// Mitsubishi GX Works2 project: 日东运输机程序   PLC: FX3U/FX3UC

PROGRAM MAIN
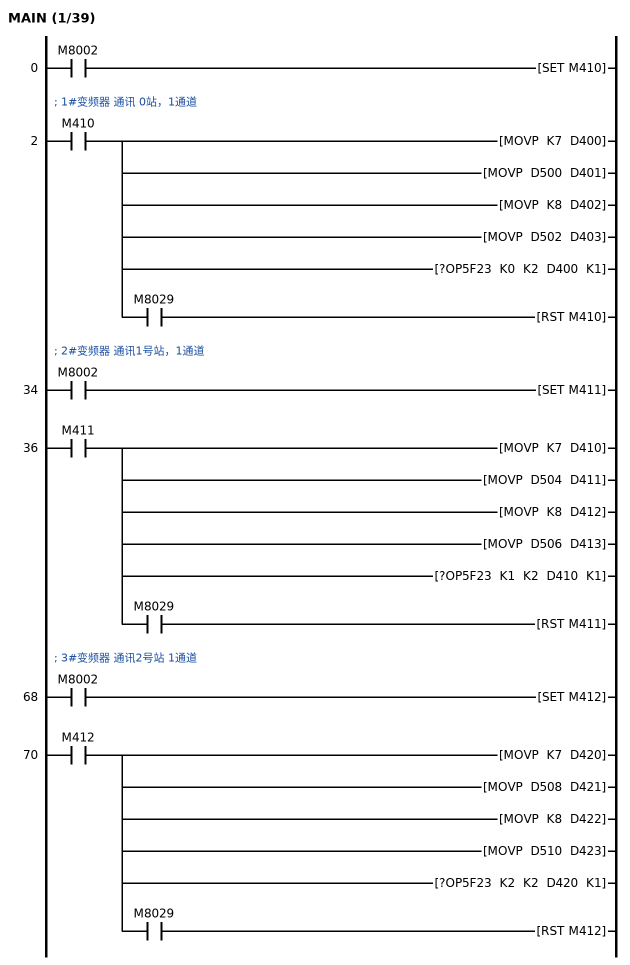
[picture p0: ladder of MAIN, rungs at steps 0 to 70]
0     LD      M8002
      SET     M410
; 1#变频器 通讯 0站，1通道
2     LD      M410
      MOVP    K7 D400
      MOVP    D500 D401
      MOVP    K8 D402
      MOVP    D502 D403
      ?OP5F23 K0 K2 D400 K1
        [note] 变频器参数成批写入
      AND     M8029
      RST     M410
; 2#变频器 通讯1号站，1通道
34    LD      M8002
      SET     M411
36    LD      M411
      MOVP    K7 D410
      MOVP    D504 D411
      MOVP    K8 D412
      MOVP    D506 D413
      ?OP5F23 K1 K2 D410 K1
        [note] 变频器参数成批写入
      AND     M8029
      RST     M411
; 3#变频器 通讯2号站 1通道
68    LD      M8002
      SET     M412
70    LD      M412
      MOVP    K7 D420
      MOVP    D508 D421
      MOVP    K8 D422
      MOVP    D510 D423
      ?OP5F23 K2 K2 D420 K1
        [note] 变频器参数成批写入
      AND     M8029
      RST     M412
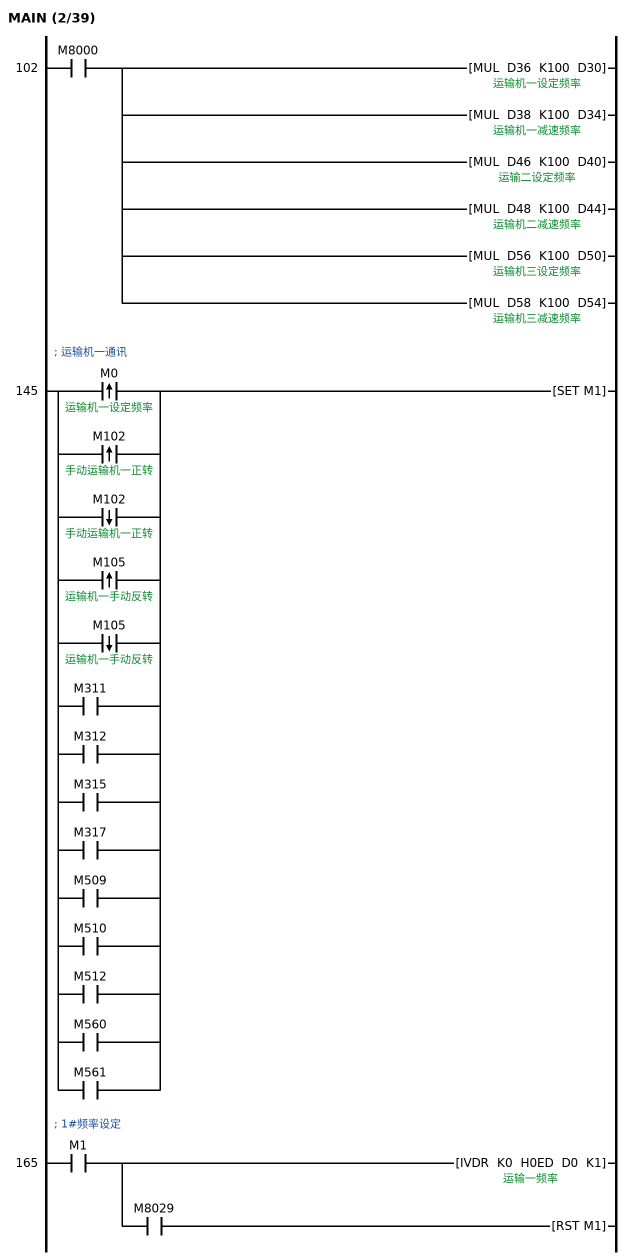
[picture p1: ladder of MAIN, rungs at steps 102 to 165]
102   LD      M8000
      MUL     D36 K100 D30  ; 运输机一设定频率
      MUL     D38 K100 D34  ; 运输机一减速频率
      MUL     D46 K100 D40  ; 运输二设定频率
      MUL     D48 K100 D44  ; 运输机二减速频率
      MUL     D56 K100 D50  ; 运输机三设定频率
      MUL     D58 K100 D54  ; 运输机三减速频率
; 运输机一通讯
145   LDP     M0  ; 运输机一设定频率
      ORP     M102  ; 手动运输机一正转
      ORF     M102  ; 手动运输机一正转
      ORP     M105  ; 运输机一手动反转
      ORF     M105  ; 运输机一手动反转
      OR      M311
      OR      M312
      OR      M315
      OR      M317
      OR      M509
      OR      M510
      OR      M512
      OR      M560
      OR      M561
      SET     M1
; 1#频率设定
165   LD      M1
      IVDR    K0 H0ED D0 K1  ; 运输一频率
      AND     M8029
      RST     M1
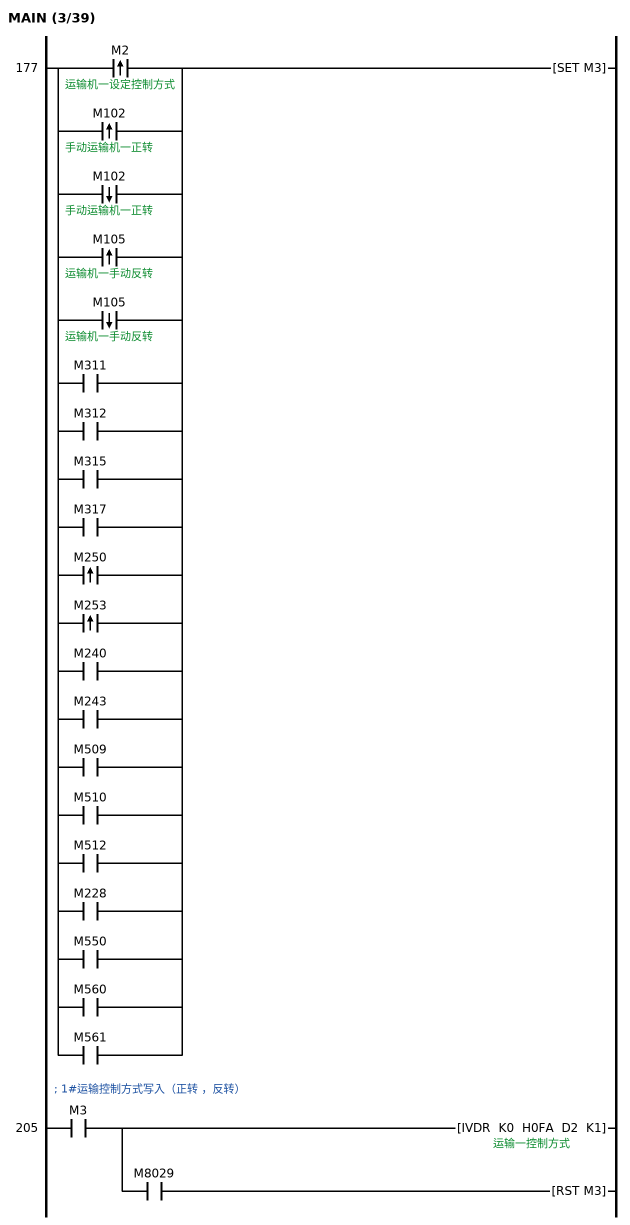
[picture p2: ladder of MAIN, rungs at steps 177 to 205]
177   LDP     M2  ; 运输机一设定控制方式
      ORP     M102  ; 手动运输机一正转
      ORF     M102  ; 手动运输机一正转
      ORP     M105  ; 运输机一手动反转
      ORF     M105  ; 运输机一手动反转
      OR      M311
      OR      M312
      OR      M315
      OR      M317
      ORP     M250
      ORP     M253
      OR      M240
      OR      M243
      OR      M509
      OR      M510
      OR      M512
      OR      M228
      OR      M550
      OR      M560
      OR      M561
      SET     M3
; 1#运输控制方式写入（正转 ，反转）
205   LD      M3
      IVDR    K0 H0FA D2 K1  ; 运输一控制方式
      AND     M8029
      RST     M3
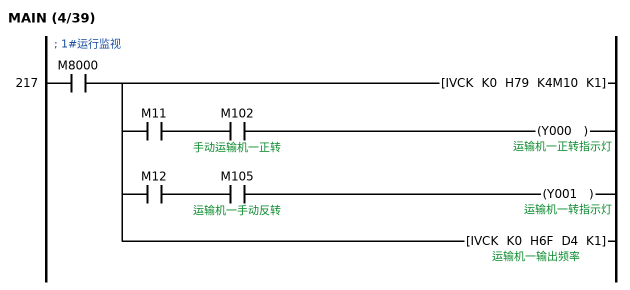
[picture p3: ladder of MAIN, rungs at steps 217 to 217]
; 1#运行监视
217   LD      M8000
      IVCK    K0 H79 K4M10 K1  ; 运输机一运行显示
      MPS
      AND     M11
      AND     M102  ; 手动运输机一正转
      OUT     Y000  ; 运输机一正转指示灯
      MRD
      AND     M12
      AND     M105  ; 运输机一手动反转
      OUT     Y001  ; 运输机一转指示灯
      MPP
      IVCK    K0 H6F D4 K1  ; 运输机一输出频率
        [note] 1#输出频率读取
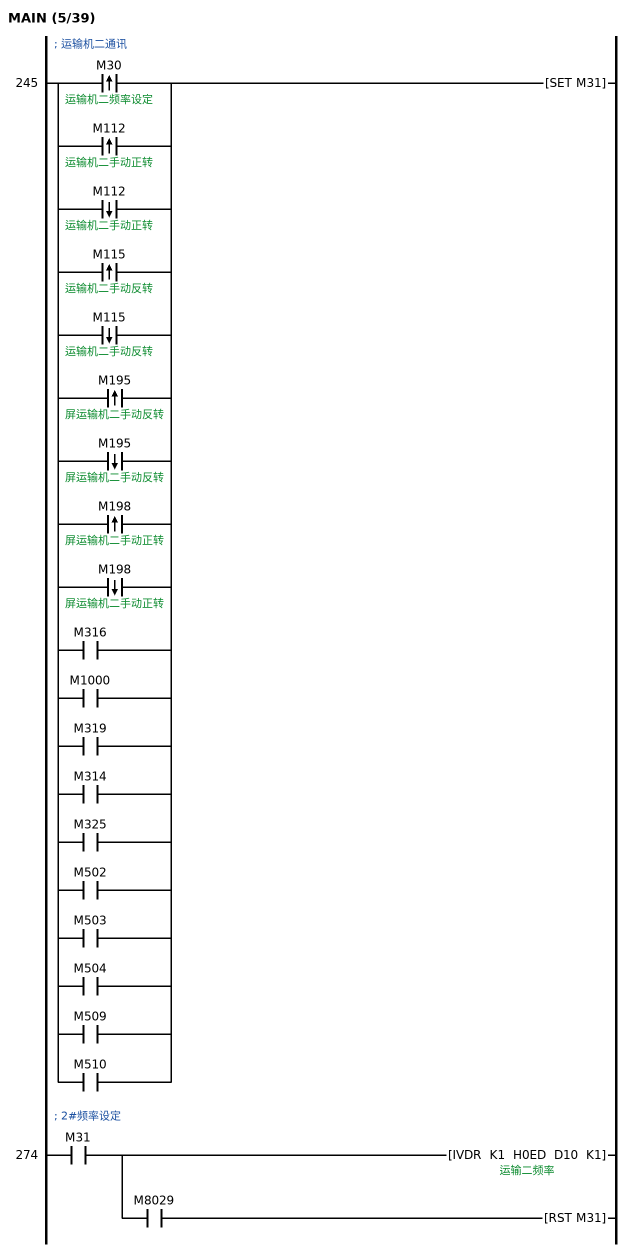
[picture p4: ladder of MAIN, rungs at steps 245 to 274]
; 运输机二通讯
245   LDP     M30  ; 运输机二频率设定
      ORP     M112  ; 运输机二手动正转
      ORF     M112  ; 运输机二手动正转
      ORP     M115  ; 运输机二手动反转
      ORF     M115  ; 运输机二手动反转
      ORP     M195  ; 屏运输机二手动反转
      ORF     M195  ; 屏运输机二手动反转
      ORP     M198  ; 屏运输机二手动正转
      ORF     M198  ; 屏运输机二手动正转
      OR      M316
      OR      M1000
      OR      M319
      OR      M314
      OR      M325
      OR      M502
      OR      M503
      OR      M504
      OR      M509
      OR      M510
      SET     M31
; 2#频率设定
274   LD      M31
      IVDR    K1 H0ED D10 K1  ; 运输二频率
      AND     M8029
      RST     M31
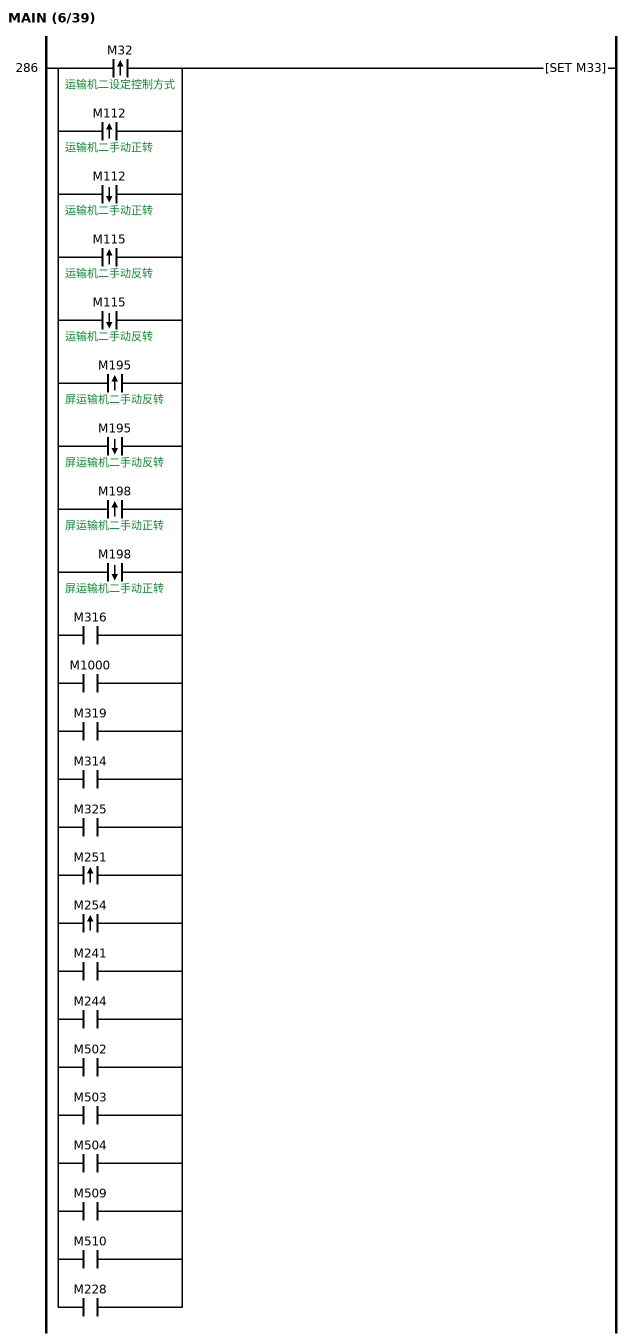
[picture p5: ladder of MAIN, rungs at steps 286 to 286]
286   LDP     M32  ; 运输机二设定控制方式
      ORP     M112  ; 运输机二手动正转
      ORF     M112  ; 运输机二手动正转
      ORP     M115  ; 运输机二手动反转
      ORF     M115  ; 运输机二手动反转
      ORP     M195  ; 屏运输机二手动反转
      ORF     M195  ; 屏运输机二手动反转
      ORP     M198  ; 屏运输机二手动正转
      ORF     M198  ; 屏运输机二手动正转
      OR      M316
      OR      M1000
      OR      M319
      OR      M314
      OR      M325
      ORP     M251
      ORP     M254
      OR      M241
      OR      M244
      OR      M502
      OR      M503
      OR      M504
      OR      M509
      OR      M510
      OR      M228
      SET     M33
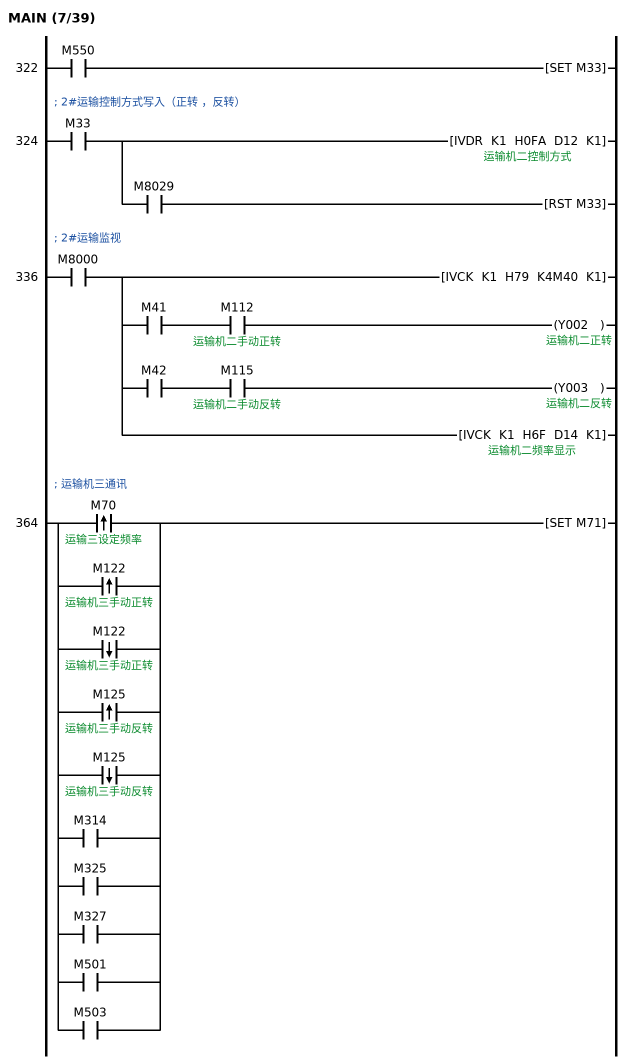
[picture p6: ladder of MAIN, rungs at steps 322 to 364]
322   LD      M550
      SET     M33
; 2#运输控制方式写入（正转 ，反转）
324   LD      M33
      IVDR    K1 H0FA D12 K1  ; 运输机二控制方式
      AND     M8029
      RST     M33
; 2#运输监视
336   LD      M8000
      IVCK    K1 H79 K4M40 K1  ; 运输机二运行显示
      MPS
      AND     M41
      AND     M112  ; 运输机二手动正转
      OUT     Y002  ; 运输机二正转
      MRD
      AND     M42
      AND     M115  ; 运输机二手动反转
      OUT     Y003  ; 运输机二反转
      MPP
      IVCK    K1 H6F D14 K1  ; 运输机二频率显示
; 运输机三通讯
364   LDP     M70  ; 运输三设定频率
      ORP     M122  ; 运输机三手动正转
      ORF     M122  ; 运输机三手动正转
      ORP     M125  ; 运输机三手动反转
      ORF     M125  ; 运输机三手动反转
      OR      M314
      OR      M325
      OR      M327
      OR      M501
      OR      M503
      SET     M71
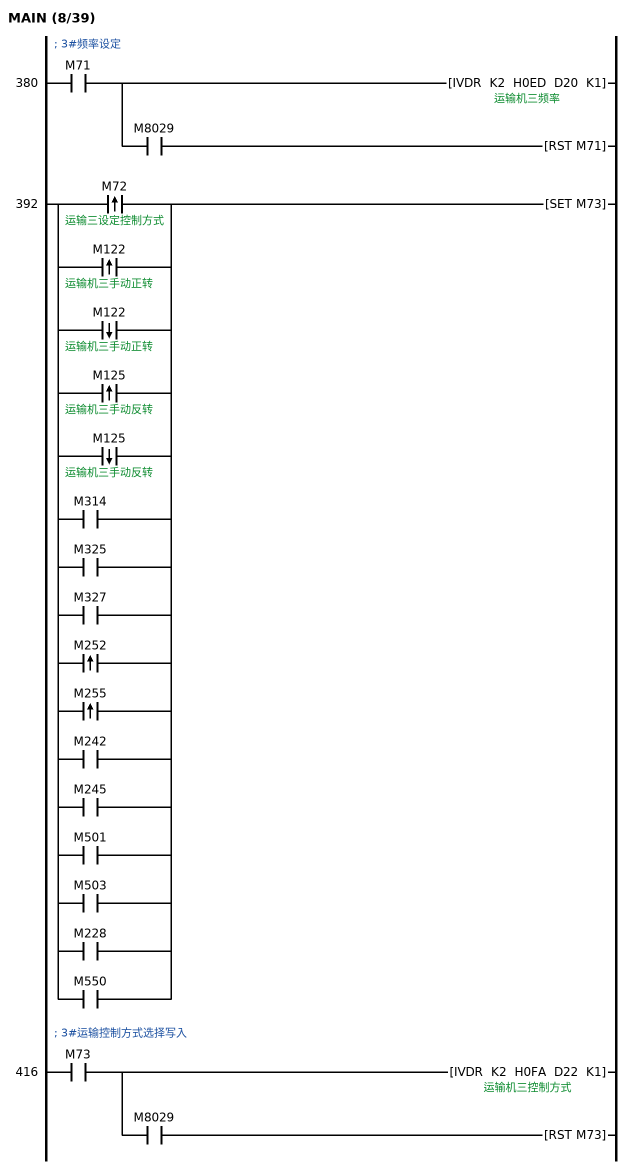
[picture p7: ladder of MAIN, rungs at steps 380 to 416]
; 3#频率设定
380   LD      M71
      IVDR    K2 H0ED D20 K1  ; 运输机三频率
      AND     M8029
      RST     M71
392   LDP     M72  ; 运输三设定控制方式
      ORP     M122  ; 运输机三手动正转
      ORF     M122  ; 运输机三手动正转
      ORP     M125  ; 运输机三手动反转
      ORF     M125  ; 运输机三手动反转
      OR      M314
      OR      M325
      OR      M327
      ORP     M252
      ORP     M255
      OR      M242
      OR      M245
      OR      M501
      OR      M503
      OR      M228
      OR      M550
      SET     M73
; 3#运输控制方式选择写入
416   LD      M73
      IVDR    K2 H0FA D22 K1  ; 运输机三控制方式
      AND     M8029
      RST     M73
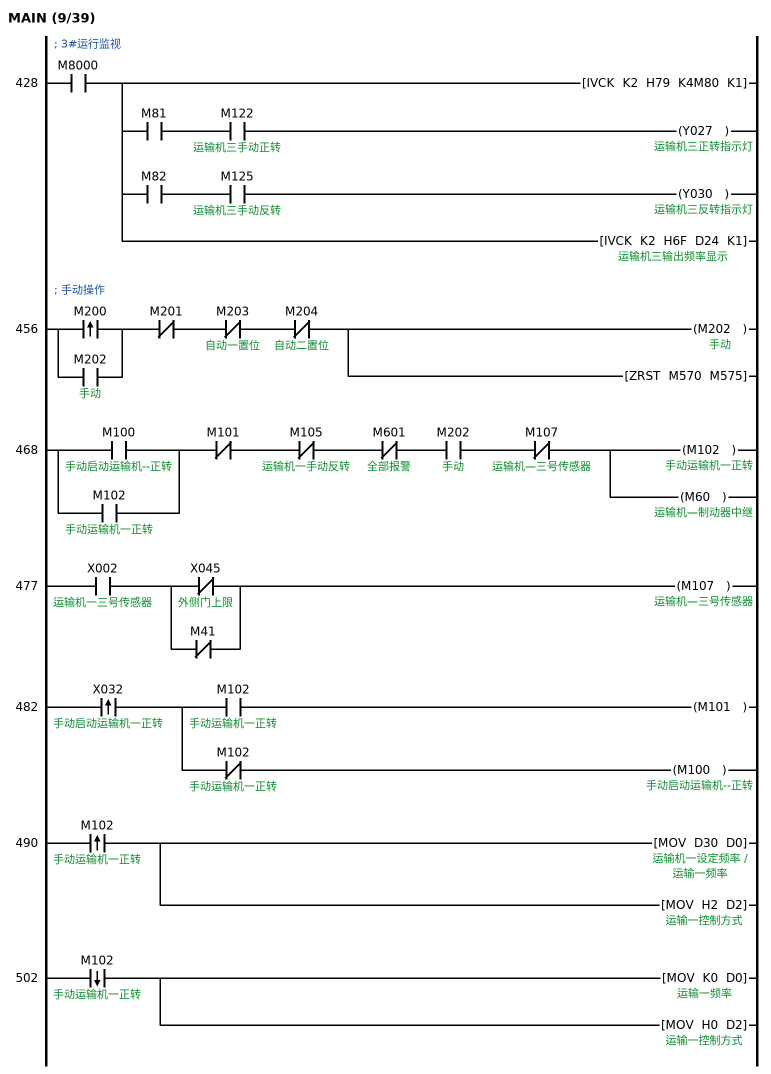
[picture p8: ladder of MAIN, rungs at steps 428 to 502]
; 3#运行监视
428   LD      M8000
      IVCK    K2 H79 K4M80 K1  ; 运输机三运行显示
      MPS
      AND     M81
      AND     M122  ; 运输机三手动正转
      OUT     Y027  ; 运输机三正转指示灯
      MRD
      AND     M82
      AND     M125  ; 运输机三手动反转
      OUT     Y030  ; 运输机三反转指示灯
      MPP
      IVCK    K2 H6F D24 K1  ; 运输机三输出频率显示
; 手动操作
456   LDP     M200
      OR      M202  ; 手动
      ANI     M201
      ANI     M203  ; 自动一置位
      ANI     M204  ; 自动二置位
      OUT     M202  ; 手动
      ZRST    M570 M575
468   LD      M100  ; 手动启动运输机--正转
      OR      M102  ; 手动运输机一正转
      ANI     M101
      ANI     M105  ; 运输机一手动反转
      ANI     M601  ; 全部报警
      AND     M202  ; 手动
      ANI     M107  ; 运输机—三号传感器
      OUT     M102  ; 手动运输机一正转
      OUT     M60  ; 运输机—制动器中继
477   LD      X002  ; 运输机一三号传感器
      LDI     X045  ; 外侧门上限
      ORI     M41
      ANB
      OUT     M107  ; 运输机—三号传感器
482   LDP     X032  ; 手动启动运输机一正转
      MPS
      AND     M102  ; 手动运输机一正转
      OUT     M101
      MPP
      ANI     M102  ; 手动运输机一正转
      OUT     M100  ; 手动启动运输机--正转
490   LDP     M102  ; 手动运输机一正转
      MOV     D30 D0
      MOV     H2 D2
        [note] 1#运输机正转写入
502   LDF     M102  ; 手动运输机一正转
      MOV     K0 D0
      MOV     H0 D2
        [note] 1#运输机停止写入
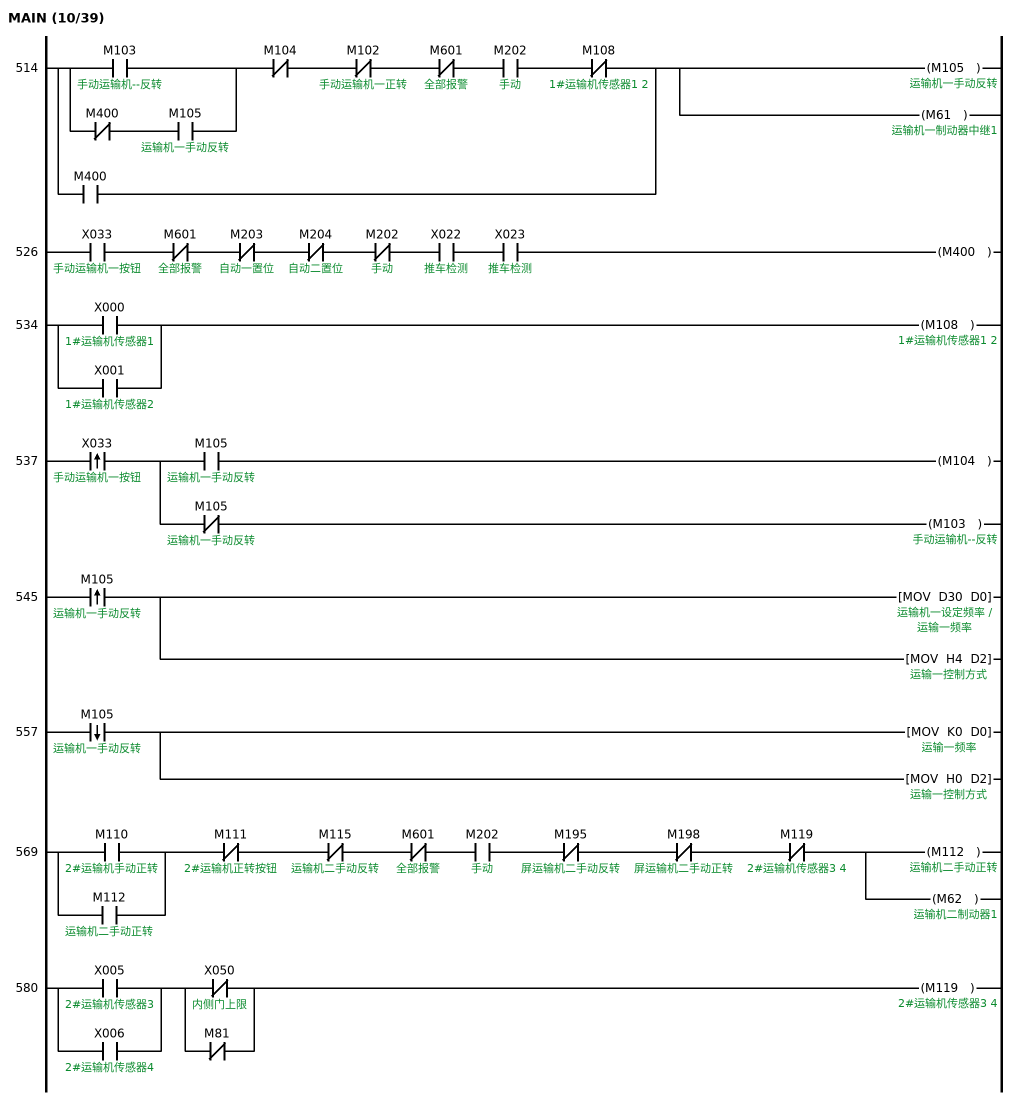
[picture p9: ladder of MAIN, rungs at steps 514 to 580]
514   LD      M103  ; 手动运输机--反转
      LDI     M400
      AND     M105  ; 运输机一手动反转
      ORB
      ANI     M104
      ANI     M102  ; 手动运输机一正转
      ANI     M601  ; 全部报警
      AND     M202  ; 手动
      ANI     M108  ; 1#运输机传感器1 2
      OR      M400
      OUT     M105  ; 运输机一手动反转
      OUT     M61  ; 运输机一制动器中继1
526   LD      X033  ; 手动运输机一按钮
      ANI     M601  ; 全部报警
      ANI     M203  ; 自动一置位
      ANI     M204  ; 自动二置位
      ANI     M202  ; 手动
      AND     X022  ; 推车检测
      AND     X023  ; 推车检测
      OUT     M400
534   LD      X000  ; 1#运输机传感器1
      OR      X001  ; 1#运输机传感器2
      OUT     M108  ; 1#运输机传感器1 2
537   LDP     X033  ; 手动运输机一按钮
      MPS
      AND     M105  ; 运输机一手动反转
      OUT     M104
      MPP
      ANI     M105  ; 运输机一手动反转
      OUT     M103  ; 手动运输机--反转
545   LDP     M105  ; 运输机一手动反转
      MOV     D30 D0
      MOV     H4 D2
        [note] 1#运输机反转写入
557   LDF     M105  ; 运输机一手动反转
      MOV     K0 D0
      MOV     H0 D2
        [note] 1#运输机停止写入
569   LD      M110  ; 2#运输机手动正转
      OR      M112  ; 运输机二手动正转
      ANI     M111  ; 2#运输机正转按钮
      ANI     M115  ; 运输机二手动反转
      ANI     M601  ; 全部报警
      AND     M202  ; 手动
      ANI     M195  ; 屏运输机二手动反转
      ANI     M198  ; 屏运输机二手动正转
      ANI     M119  ; 2#运输机传感器3 4
      OUT     M112  ; 运输机二手动正转
      OUT     M62  ; 运输机二制动器1
580   LD      X005  ; 2#运输机传感器3
      OR      X006  ; 2#运输机传感器4
      LDI     X050  ; 内侧门上限
      ORI     M81
      ANB
      OUT     M119  ; 2#运输机传感器3 4
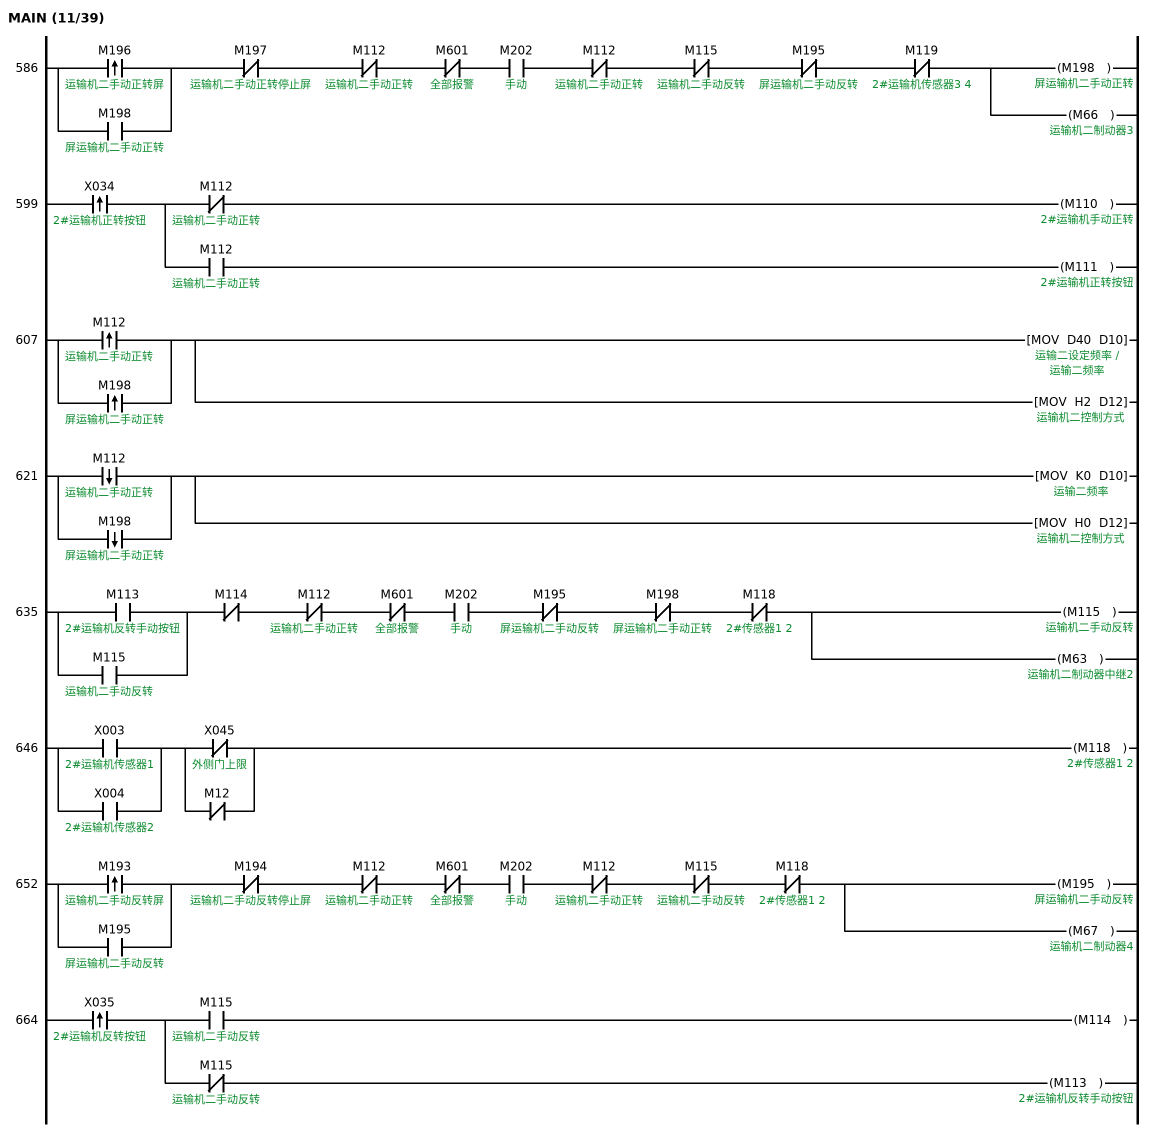
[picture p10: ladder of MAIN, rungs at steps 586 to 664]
586   LDP     M196  ; 运输机二手动正转屏
      OR      M198  ; 屏运输机二手动正转
      ANI     M197  ; 运输机二手动正转停止屏
      ANI     M112  ; 运输机二手动正转
      ANI     M601  ; 全部报警
      AND     M202  ; 手动
      ANI     M112  ; 运输机二手动正转
      ANI     M115  ; 运输机二手动反转
      ANI     M195  ; 屏运输机二手动反转
      ANI     M119  ; 2#运输机传感器3 4
      OUT     M198  ; 屏运输机二手动正转
      OUT     M66  ; 运输机二制动器3
599   LDP     X034  ; 2#运输机正转按钮
      MPS
      ANI     M112  ; 运输机二手动正转
      OUT     M110  ; 2#运输机手动正转
      MPP
      AND     M112  ; 运输机二手动正转
      OUT     M111  ; 2#运输机正转按钮
607   LDP     M112  ; 运输机二手动正转
      ORP     M198  ; 屏运输机二手动正转
      MOV     D40 D10
      MOV     H2 D12
        [note] 2#运输机正转写入
621   LDF     M112  ; 运输机二手动正转
      ORF     M198  ; 屏运输机二手动正转
      MOV     K0 D10
      MOV     H0 D12
        [note] 2#运输机停止写入
635   LD      M113  ; 2#运输机反转手动按钮
      OR      M115  ; 运输机二手动反转
      ANI     M114
      ANI     M112  ; 运输机二手动正转
      ANI     M601  ; 全部报警
      AND     M202  ; 手动
      ANI     M195  ; 屏运输机二手动反转
      ANI     M198  ; 屏运输机二手动正转
      ANI     M118  ; 2#传感器1 2
      OUT     M115  ; 运输机二手动反转
      OUT     M63  ; 运输机二制动器中继2
646   LD      X003  ; 2#运输机传感器1
      OR      X004  ; 2#运输机传感器2
      LDI     X045  ; 外侧门上限
      ORI     M12
      ANB
      OUT     M118  ; 2#传感器1 2
652   LDP     M193  ; 运输机二手动反转屏
      OR      M195  ; 屏运输机二手动反转
      ANI     M194  ; 运输机二手动反转停止屏
      ANI     M112  ; 运输机二手动正转
      ANI     M601  ; 全部报警
      AND     M202  ; 手动
      ANI     M112  ; 运输机二手动正转
      ANI     M115  ; 运输机二手动反转
      ANI     M118  ; 2#传感器1 2
      OUT     M195  ; 屏运输机二手动反转
      OUT     M67  ; 运输机二制动器4
664   LDP     X035  ; 2#运输机反转按钮
      MPS
      AND     M115  ; 运输机二手动反转
      OUT     M114
      MPP
      ANI     M115  ; 运输机二手动反转
      OUT     M113  ; 2#运输机反转手动按钮
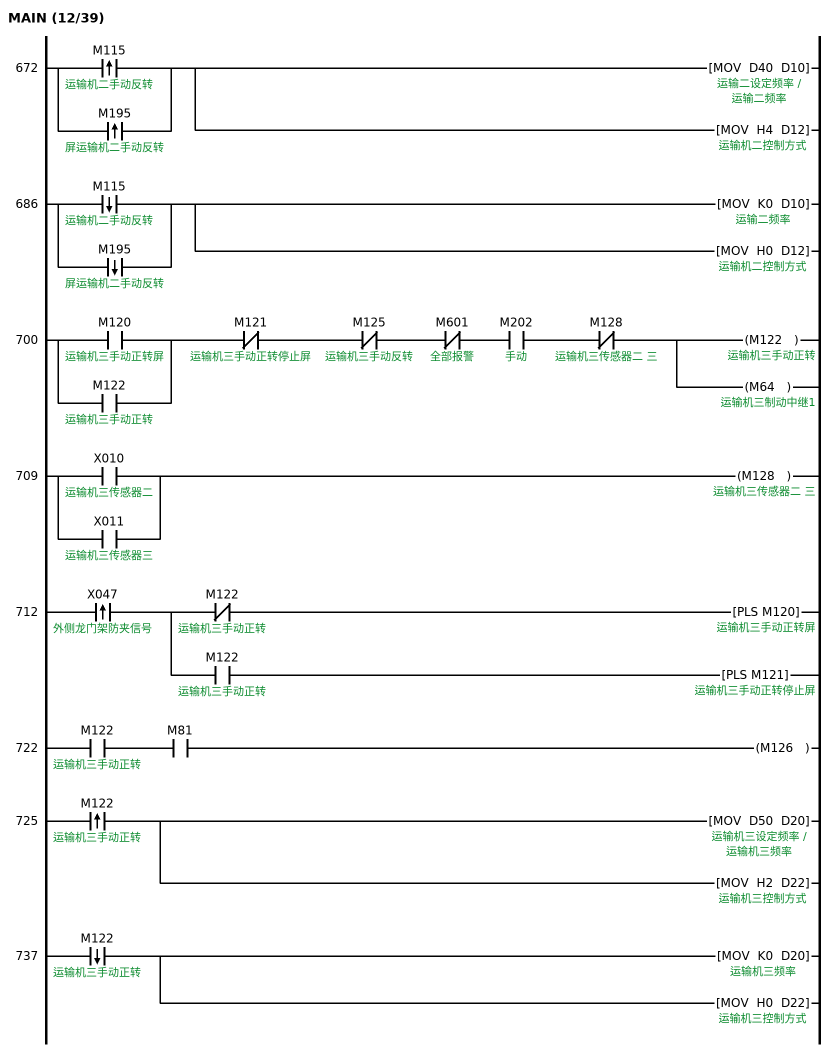
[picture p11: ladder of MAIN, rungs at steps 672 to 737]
672   LDP     M115  ; 运输机二手动反转
      ORP     M195  ; 屏运输机二手动反转
      MOV     D40 D10
      MOV     H4 D12
        [note] 2#运输机反转写入
686   LDF     M115  ; 运输机二手动反转
      ORF     M195  ; 屏运输机二手动反转
      MOV     K0 D10
      MOV     H0 D12
        [note] 2#运输机停止写入
700   LD      M120  ; 运输机三手动正转屏
      OR      M122  ; 运输机三手动正转
      ANI     M121  ; 运输机三手动正转停止屏
      ANI     M125  ; 运输机三手动反转
      ANI     M601  ; 全部报警
      AND     M202  ; 手动
      ANI     M128  ; 运输机三传感器二 三
      OUT     M122  ; 运输机三手动正转
      OUT     M64  ; 运输机三制动中继1
709   LD      X010  ; 运输机三传感器二
      OR      X011  ; 运输机三传感器三
      OUT     M128  ; 运输机三传感器二 三
712   LDP     X047  ; 外侧龙门架防夹信号
      MPS
      ANI     M122  ; 运输机三手动正转
      PLS     M120  ; 运输机三手动正转屏
      MPP
      AND     M122  ; 运输机三手动正转
      PLS     M121  ; 运输机三手动正转停止屏
722   LD      M122  ; 运输机三手动正转
      AND     M81
      OUT     M126
725   LDP     M122  ; 运输机三手动正转
      MOV     D50 D20
      MOV     H2 D22
        [note] 3#运输机正转写入
737   LDF     M122  ; 运输机三手动正转
      MOV     K0 D20
      MOV     H0 D22
        [note] 3#运输机停止写入
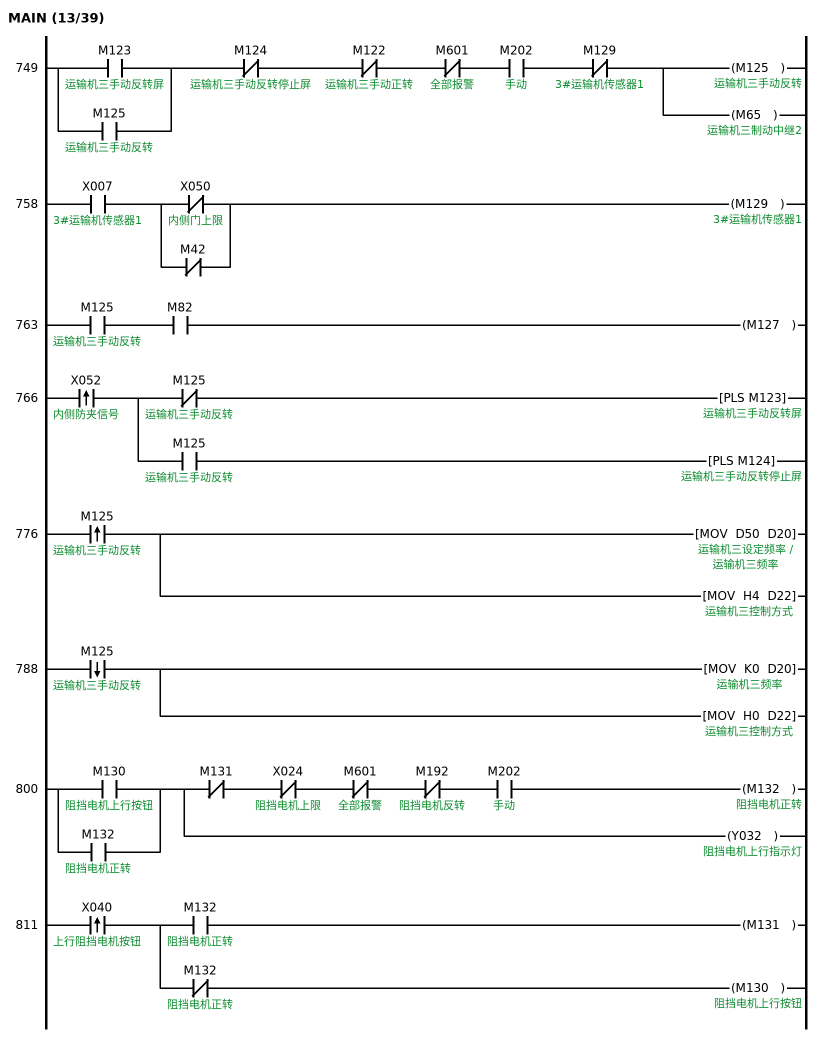
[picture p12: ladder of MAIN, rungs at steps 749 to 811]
749   LD      M123  ; 运输机三手动反转屏
      OR      M125  ; 运输机三手动反转
      ANI     M124  ; 运输机三手动反转停止屏
      ANI     M122  ; 运输机三手动正转
      ANI     M601  ; 全部报警
      AND     M202  ; 手动
      ANI     M129  ; 3#运输机传感器1
      OUT     M125  ; 运输机三手动反转
      OUT     M65  ; 运输机三制动中继2
758   LD      X007  ; 3#运输机传感器1
      LDI     X050  ; 内侧门上限
      ORI     M42
      ANB
      OUT     M129  ; 3#运输机传感器1
763   LD      M125  ; 运输机三手动反转
      AND     M82
      OUT     M127
766   LDP     X052  ; 内侧防夹信号
      MPS
      ANI     M125  ; 运输机三手动反转
      PLS     M123  ; 运输机三手动反转屏
      MPP
      AND     M125  ; 运输机三手动反转
      PLS     M124  ; 运输机三手动反转停止屏
776   LDP     M125  ; 运输机三手动反转
      MOV     D50 D20
      MOV     H4 D22
        [note] 3#运输机反转写入
788   LDF     M125  ; 运输机三手动反转
      MOV     K0 D20
      MOV     H0 D22
        [note] 3#运输机停止写入
800   LD      M130  ; 阻挡电机上行按钮
      OR      M132  ; 阻挡电机正转
      MPS
      ANI     M131
      ANI     X024  ; 阻挡电机上限
      ANI     M601  ; 全部报警
      ANI     M192  ; 阻挡电机反转
      AND     M202  ; 手动
      OUT     M132  ; 阻挡电机正转
      MPP
      OUT     Y032  ; 阻挡电机上行指示灯
811   LDP     X040  ; 上行阻挡电机按钮
      MPS
      AND     M132  ; 阻挡电机正转
      OUT     M131
      MPP
      ANI     M132  ; 阻挡电机正转
      OUT     M130  ; 阻挡电机上行按钮
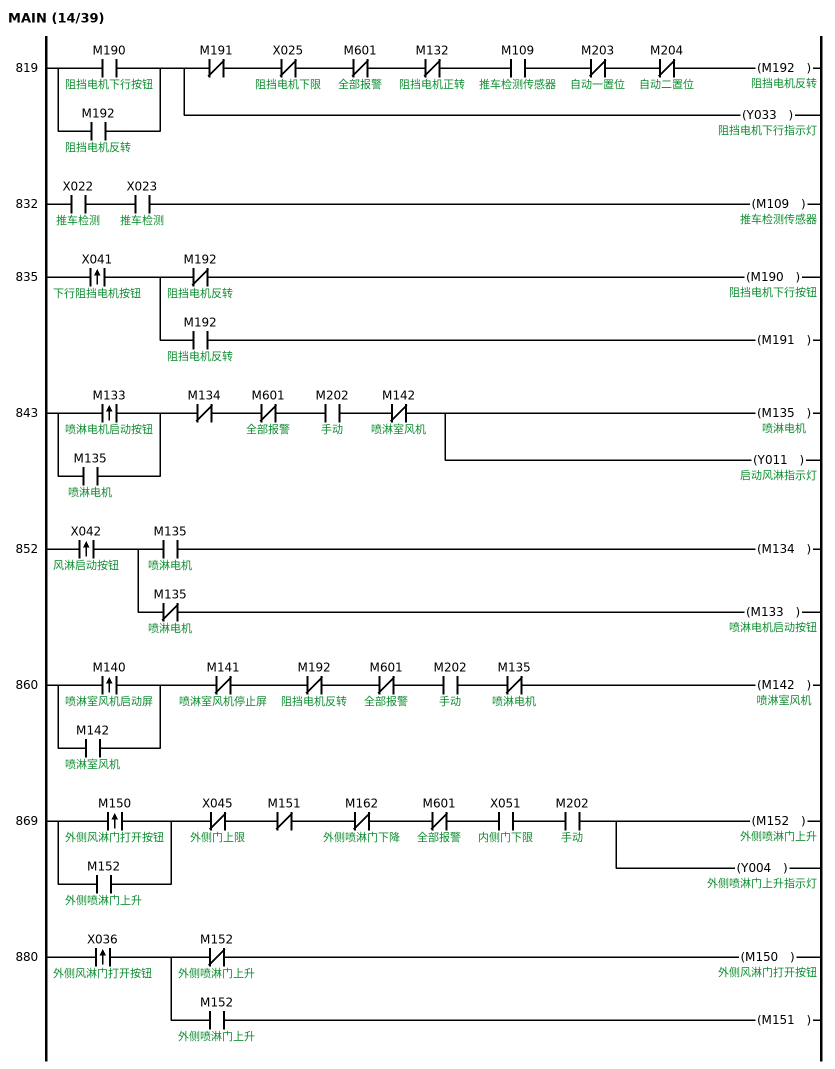
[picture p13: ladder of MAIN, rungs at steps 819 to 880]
819   LD      M190  ; 阻挡电机下行按钮
      OR      M192  ; 阻挡电机反转
      MPS
      ANI     M191
      ANI     X025  ; 阻挡电机下限
      ANI     M601  ; 全部报警
      ANI     M132  ; 阻挡电机正转
      AND     M109  ; 推车检测传感器
      ANI     M203  ; 自动一置位
      ANI     M204  ; 自动二置位
      OUT     M192  ; 阻挡电机反转
      MPP
      OUT     Y033  ; 阻挡电机下行指示灯
832   LD      X022  ; 推车检测
      AND     X023  ; 推车检测
      OUT     M109  ; 推车检测传感器
835   LDP     X041  ; 下行阻挡电机按钮
      MPS
      ANI     M192  ; 阻挡电机反转
      OUT     M190  ; 阻挡电机下行按钮
      MPP
      AND     M192  ; 阻挡电机反转
      OUT     M191
843   LDP     M133  ; 喷淋电机启动按钮
      OR      M135  ; 喷淋电机
      ANI     M134
      ANI     M601  ; 全部报警
      AND     M202  ; 手动
      ANI     M142  ; 喷淋室风机
      OUT     M135  ; 喷淋电机
      OUT     Y011  ; 启动风淋指示灯
852   LDP     X042  ; 风淋启动按钮
      MPS
      AND     M135  ; 喷淋电机
      OUT     M134
      MPP
      ANI     M135  ; 喷淋电机
      OUT     M133  ; 喷淋电机启动按钮
860   LDP     M140  ; 喷淋室风机启动屏
      OR      M142  ; 喷淋室风机
      ANI     M141  ; 喷淋室风机停止屏
      ANI     M192  ; 阻挡电机反转
      ANI     M601  ; 全部报警
      AND     M202  ; 手动
      ANI     M135  ; 喷淋电机
      OUT     M142  ; 喷淋室风机
869   LDP     M150  ; 外侧风淋门打开按钮
      OR      M152  ; 外侧喷淋门上升
      ANI     X045  ; 外侧门上限
      ANI     M151
      ANI     M162  ; 外侧喷淋门下降
      ANI     M601  ; 全部报警
      AND     X051  ; 内侧门下限
      AND     M202  ; 手动
      OUT     M152  ; 外侧喷淋门上升
      OUT     Y004  ; 外侧喷淋门上升指示灯
880   LDP     X036  ; 外侧风淋门打开按钮
      MPS
      ANI     M152  ; 外侧喷淋门上升
      OUT     M150  ; 外侧风淋门打开按钮
      MPP
      AND     M152  ; 外侧喷淋门上升
      OUT     M151
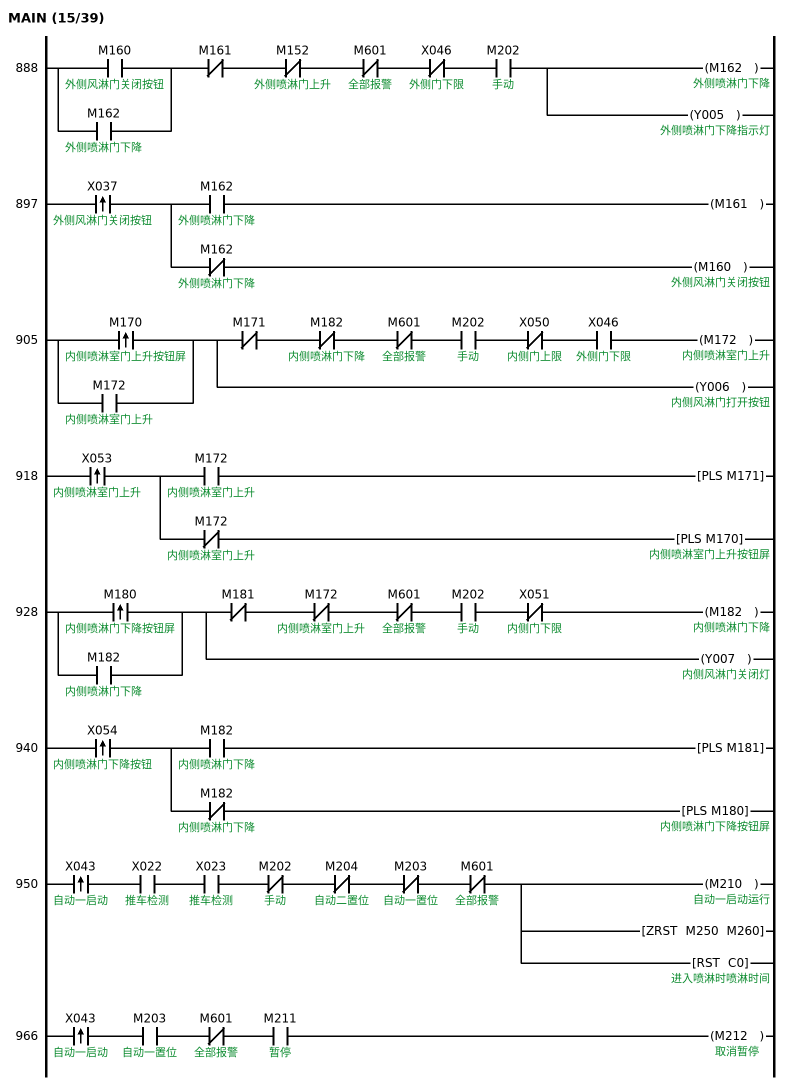
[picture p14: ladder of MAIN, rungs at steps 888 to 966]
888   LD      M160  ; 外侧风淋门关闭按钮
      OR      M162  ; 外侧喷淋门下降
      ANI     M161
      ANI     M152  ; 外侧喷淋门上升
      ANI     M601  ; 全部报警
      ANI     X046  ; 外侧门下限
      AND     M202  ; 手动
      OUT     M162  ; 外侧喷淋门下降
      OUT     Y005  ; 外侧喷淋门下降指示灯
897   LDP     X037  ; 外侧风淋门关闭按钮
      MPS
      AND     M162  ; 外侧喷淋门下降
      OUT     M161
      MPP
      ANI     M162  ; 外侧喷淋门下降
      OUT     M160  ; 外侧风淋门关闭按钮
905   LDP     M170  ; 内侧喷淋室门上升按钮屏
      OR      M172  ; 内侧喷淋室门上升
      MPS
      ANI     M171
      ANI     M182  ; 内侧喷淋门下降
      ANI     M601  ; 全部报警
      AND     M202  ; 手动
      ANI     X050  ; 内侧门上限
      AND     X046  ; 外侧门下限
      OUT     M172  ; 内侧喷淋室门上升
      MPP
      OUT     Y006  ; 内侧风淋门打开按钮
918   LDP     X053  ; 内侧喷淋室门上升
      MPS
      AND     M172  ; 内侧喷淋室门上升
      PLS     M171
      MPP
      ANI     M172  ; 内侧喷淋室门上升
      PLS     M170  ; 内侧喷淋室门上升按钮屏
928   LDP     M180  ; 内侧喷淋门下降按钮屏
      OR      M182  ; 内侧喷淋门下降
      MPS
      ANI     M181
      ANI     M172  ; 内侧喷淋室门上升
      ANI     M601  ; 全部报警
      AND     M202  ; 手动
      ANI     X051  ; 内侧门下限
      OUT     M182  ; 内侧喷淋门下降
      MPP
      OUT     Y007  ; 内侧风淋门关闭灯
940   LDP     X054  ; 内侧喷淋门下降按钮
      MPS
      AND     M182  ; 内侧喷淋门下降
      PLS     M181
      MPP
      ANI     M182  ; 内侧喷淋门下降
      PLS     M180  ; 内侧喷淋门下降按钮屏
950   LDP     X043  ; 自动一启动
      AND     X022  ; 推车检测
      AND     X023  ; 推车检测
      ANI     M202  ; 手动
      ANI     M204  ; 自动二置位
      ANI     M203  ; 自动一置位
      ANI     M601  ; 全部报警
      OUT     M210  ; 自动一启动运行
      ZRST    M250 M260
      RST     C0  ; 进入喷淋时喷淋时间
966   LDP     X043  ; 自动一启动
      AND     M203  ; 自动一置位
      ANI     M601  ; 全部报警
      AND     M211  ; 暂停
      OUT     M212  ; 取消暂停
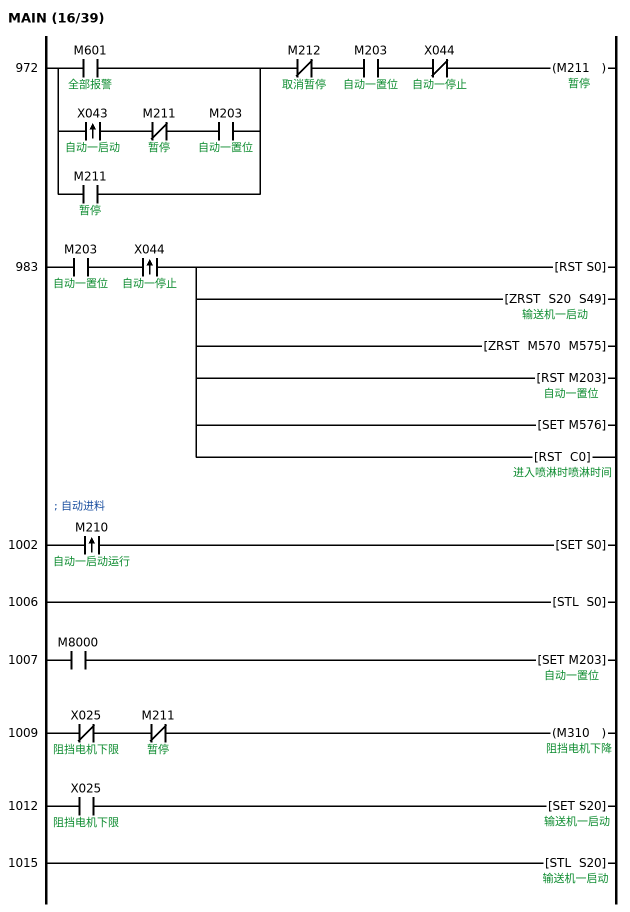
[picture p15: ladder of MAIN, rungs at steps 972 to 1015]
972   LD      M601  ; 全部报警
      LDP     X043  ; 自动一启动
      ANI     M211  ; 暂停
      AND     M203  ; 自动一置位
      ORB
      OR      M211  ; 暂停
      ANI     M212  ; 取消暂停
      AND     M203  ; 自动一置位
      ANI     X044  ; 自动一停止
      OUT     M211  ; 暂停
983   LD      M203  ; 自动一置位
      ANDP    X044  ; 自动一停止
      RST     S0
      ZRST    S20 S49  ; 输送机一启动
      ZRST    M570 M575
      RST     M203  ; 自动一置位
      SET     M576
      RST     C0  ; 进入喷淋时喷淋时间
; 自动进料
1002  LDP     M210  ; 自动一启动运行
      SET     S0
1006  STL     S0
1007  LD      M8000
      SET     M203  ; 自动一置位
1009  LDI     X025  ; 阻挡电机下限
      ANI     M211  ; 暂停
      OUT     M310  ; 阻挡电机下降
1012  LD      X025  ; 阻挡电机下限
      SET     S20  ; 输送机一启动
1015  STL     S20
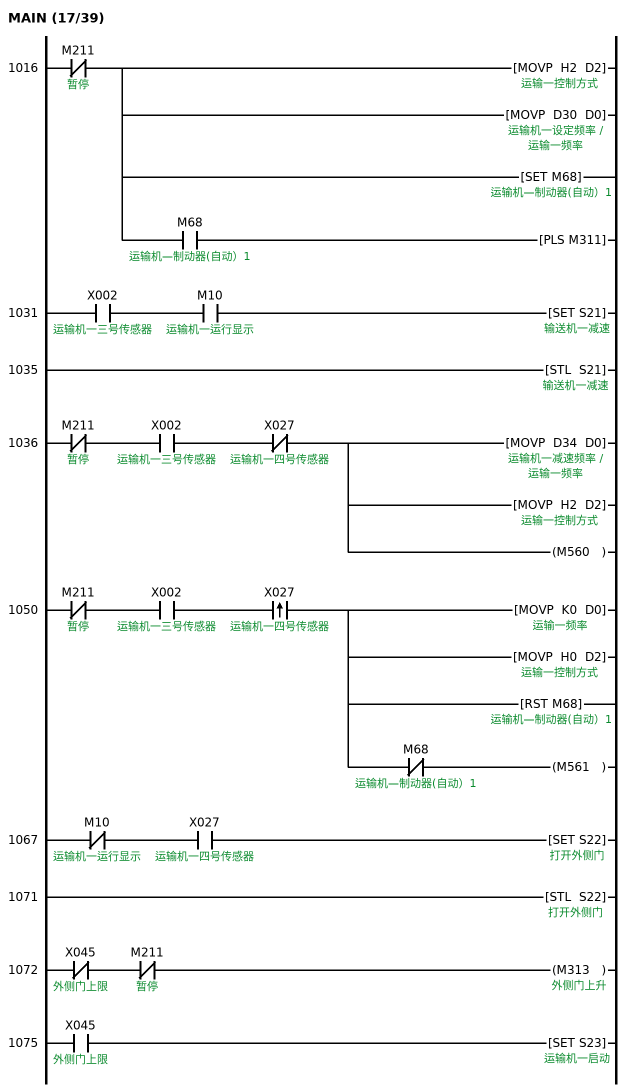
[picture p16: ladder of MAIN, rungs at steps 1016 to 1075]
1016  LDI     M211  ; 暂停
      MOVP    H2 D2
        [note] 1#运输机正转写入
      MOVP    D30 D0
      SET     M68  ; 运输机—制动器(自动）1
      AND     M68  ; 运输机—制动器(自动）1
      PLS     M311
1031  LD      X002  ; 运输机一三号传感器
      AND     M10  ; 运输机一运行显示
      SET     S21  ; 输送机一减速
1035  STL     S21
1036  LDI     M211  ; 暂停
      AND     X002  ; 运输机一三号传感器
      ANI     X027  ; 运输机一四号传感器
      MOVP    D34 D0
      MOVP    H2 D2
        [note] 1#运输机正转写入
      OUT     M560
1050  LDI     M211  ; 暂停
      AND     X002  ; 运输机一三号传感器
      ANDP    X027  ; 运输机一四号传感器
      MOVP    K0 D0
      MOVP    H0 D2
      RST     M68  ; 运输机—制动器(自动）1
      ANI     M68  ; 运输机—制动器(自动）1
      OUT     M561
1067  LDI     M10  ; 运输机一运行显示
      AND     X027  ; 运输机一四号传感器
      SET     S22  ; 打开外侧门
1071  STL     S22
1072  LDI     X045  ; 外侧门上限
      ANI     M211  ; 暂停
      OUT     M313  ; 外侧门上升
1075  LD      X045  ; 外侧门上限
      SET     S23  ; 运输机一启动
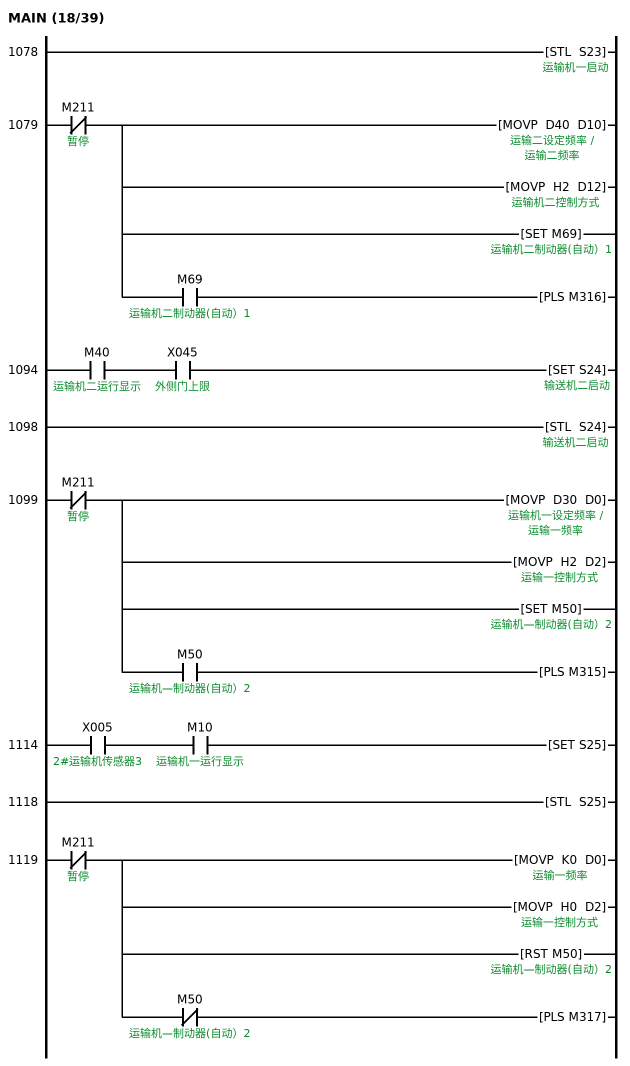
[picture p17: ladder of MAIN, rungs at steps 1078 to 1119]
1078  STL     S23
1079  LDI     M211  ; 暂停
      MOVP    D40 D10
      MOVP    H2 D12
        [note] 2#运输机正转写入
      SET     M69  ; 运输机二制动器(自动）1
      AND     M69  ; 运输机二制动器(自动）1
      PLS     M316
1094  LD      M40  ; 运输机二运行显示
      AND     X045  ; 外侧门上限
      SET     S24  ; 输送机二启动
1098  STL     S24
1099  LDI     M211  ; 暂停
      MOVP    D30 D0
      MOVP    H2 D2
        [note] 1#运输机正转写入
      SET     M50  ; 运输机—制动器(自动）2
      AND     M50  ; 运输机—制动器(自动）2
      PLS     M315
1114  LD      X005  ; 2#运输机传感器3
      AND     M10  ; 运输机一运行显示
      SET     S25
1118  STL     S25
1119  LDI     M211  ; 暂停
      MOVP    K0 D0
      MOVP    H0 D2
        [note] 1#运输机停止写入
      RST     M50  ; 运输机—制动器(自动）2
      ANI     M50  ; 运输机—制动器(自动）2
      PLS     M317
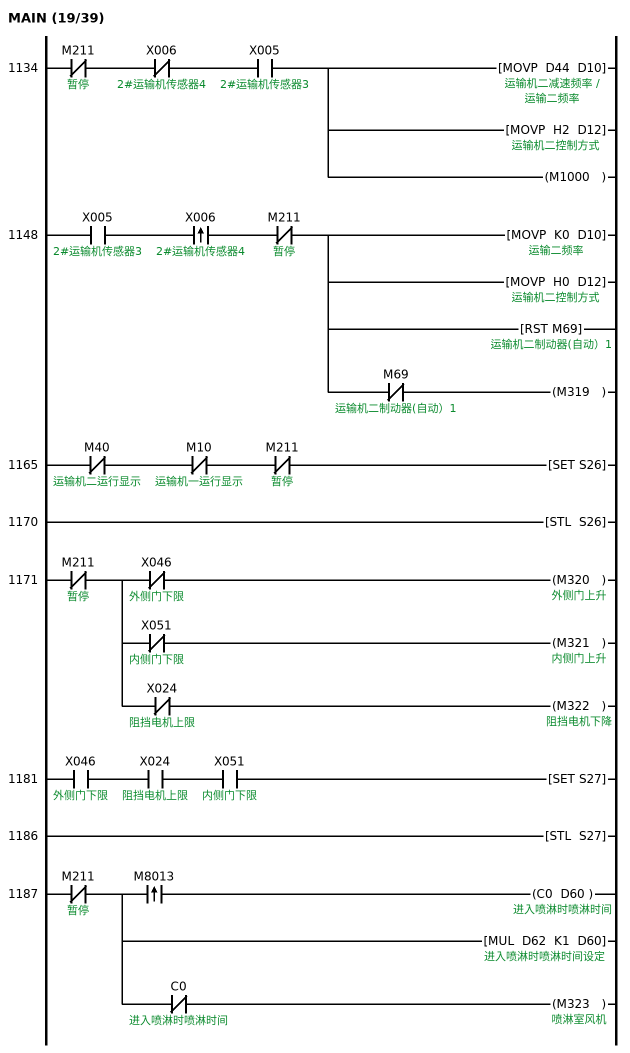
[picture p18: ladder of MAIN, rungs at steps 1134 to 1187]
1134  LDI     M211  ; 暂停
      ANI     X006  ; 2#运输机传感器4
      AND     X005  ; 2#运输机传感器3
      MOVP    D44 D10
      MOVP    H2 D12
        [note] 2#运输机正转写入
      OUT     M1000
1148  LD      X005  ; 2#运输机传感器3
      ANDP    X006  ; 2#运输机传感器4
      ANI     M211  ; 暂停
      MOVP    K0 D10
      MOVP    H0 D12
        [note] 2#运输机停止写入
      RST     M69  ; 运输机二制动器(自动）1
      ANI     M69  ; 运输机二制动器(自动）1
      OUT     M319
1165  LDI     M40  ; 运输机二运行显示
      ANI     M10  ; 运输机一运行显示
      ANI     M211  ; 暂停
      SET     S26
1170  STL     S26
1171  LDI     M211  ; 暂停
      MPS
      ANI     X046  ; 外侧门下限
      OUT     M320  ; 外侧门上升
      MRD
      ANI     X051  ; 内侧门下限
      OUT     M321  ; 内侧门上升
      MPP
      ANI     X024  ; 阻挡电机上限
      OUT     M322  ; 阻挡电机下降
1181  LD      X046  ; 外侧门下限
      AND     X024  ; 阻挡电机上限
      AND     X051  ; 内侧门下限
      SET     S27
1186  STL     S27
1187  LDI     M211  ; 暂停
      MPS
      ANDP    M8013
      OUT     C0 D60  ; 进入喷淋时喷淋时间
      MPP
      MUL     D62 K1 D60  ; 进入喷淋时喷淋时间设定
      ANI     C0  ; 进入喷淋时喷淋时间
      OUT     M323  ; 喷淋室风机
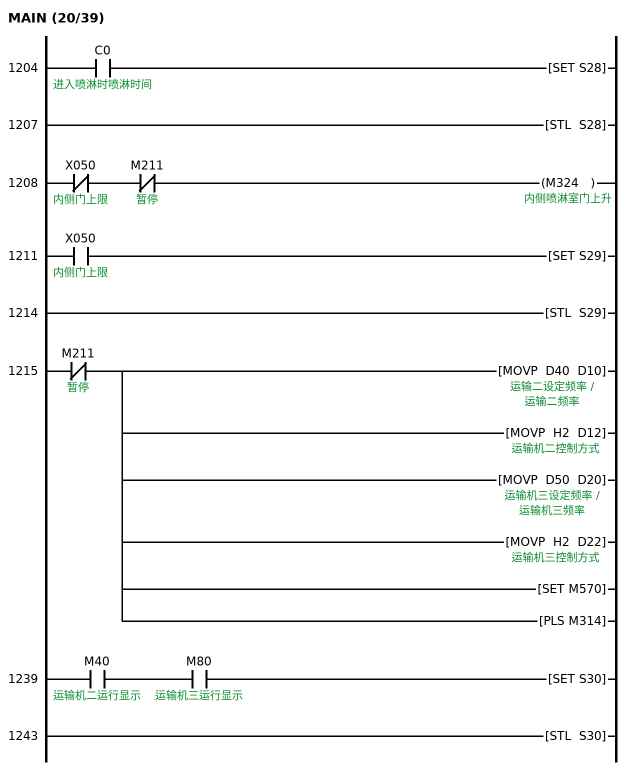
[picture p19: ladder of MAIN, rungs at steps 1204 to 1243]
1204  LD      C0  ; 进入喷淋时喷淋时间
      SET     S28
1207  STL     S28
1208  LDI     X050  ; 内侧门上限
      ANI     M211  ; 暂停
      OUT     M324  ; 内侧喷淋室门上升
1211  LD      X050  ; 内侧门上限
      SET     S29
        [note] 内侧门打开到位
1214  STL     S29
1215  LDI     M211  ; 暂停
      MOVP    D40 D10
      MOVP    H2 D12
        [note] 2#运输机正转写入
      MOVP    D50 D20
      MOVP    H2 D22
        [note] 3#运输机正转写入
      SET     M570
      PLS     M314
1239  LD      M40  ; 运输机二运行显示
      AND     M80  ; 运输机三运行显示
      SET     S30
1243  STL     S30
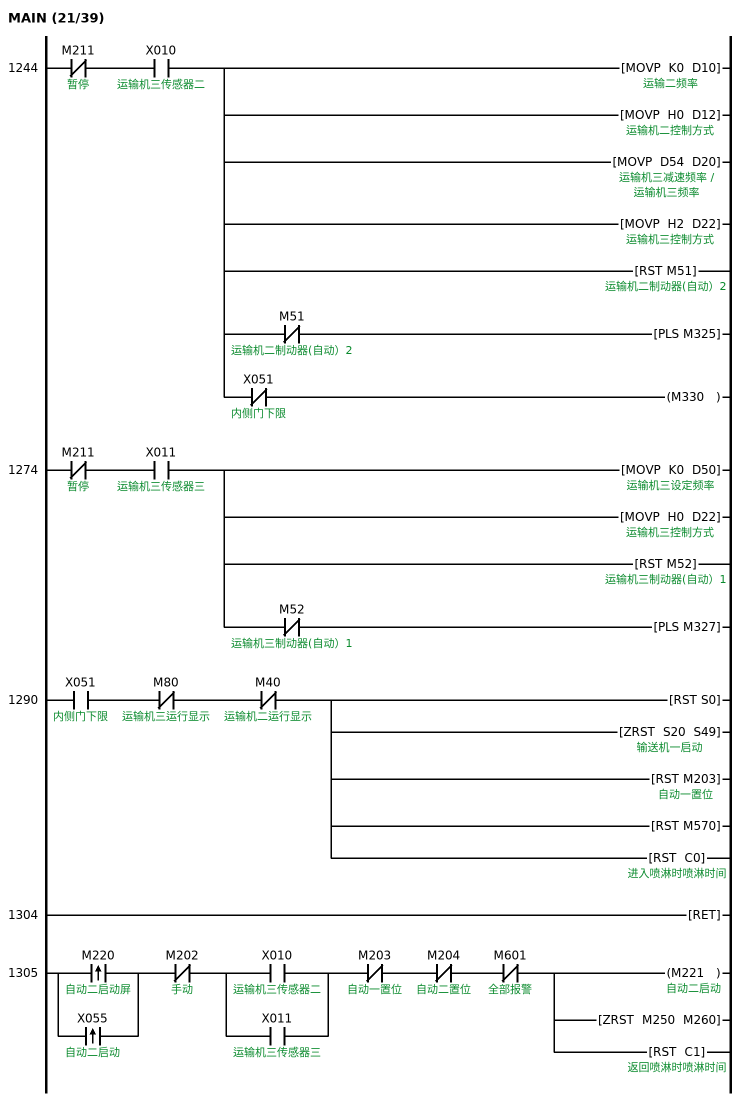
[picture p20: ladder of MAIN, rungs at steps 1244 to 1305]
1244  LDI     M211  ; 暂停
      AND     X010  ; 运输机三传感器二
      MOVP    K0 D10
      MOVP    H0 D12
        [note] 2#运输机停止写入
      MOVP    D54 D20
      MOVP    H2 D22
        [note] 3#运输机正转写入
      RST     M51  ; 运输机二制动器(自动）2
      MPS
      ANI     M51  ; 运输机二制动器(自动）2
      PLS     M325
      MPP
      ANI     X051  ; 内侧门下限
      OUT     M330
1274  LDI     M211  ; 暂停
      AND     X011  ; 运输机三传感器三
      MOVP    K0 D50
      MOVP    H0 D22
        [note] 3#运输机停止写入
      RST     M52  ; 运输机三制动器(自动）1
      ANI     M52  ; 运输机三制动器(自动）1
      PLS     M327
1290  LD      X051  ; 内侧门下限
      ANI     M80  ; 运输机三运行显示
      ANI     M40  ; 运输机二运行显示
      RST     S0
      ZRST    S20 S49
      RST     M203  ; 自动一置位
      RST     M570
      RST     C0  ; 进入喷淋时喷淋时间
1304  RET
1305  LDP     M220  ; 自动二启动屏
      ORP     X055  ; 自动二启动
      ANI     M202  ; 手动
      LD      X010  ; 运输机三传感器二
      OR      X011  ; 运输机三传感器三
      ANB
      ANI     M203  ; 自动一置位
      ANI     M204  ; 自动二置位
      ANI     M601  ; 全部报警
      OUT     M221  ; 自动二启动
      ZRST    M250 M260
      RST     C1  ; 返回喷淋时喷淋时间
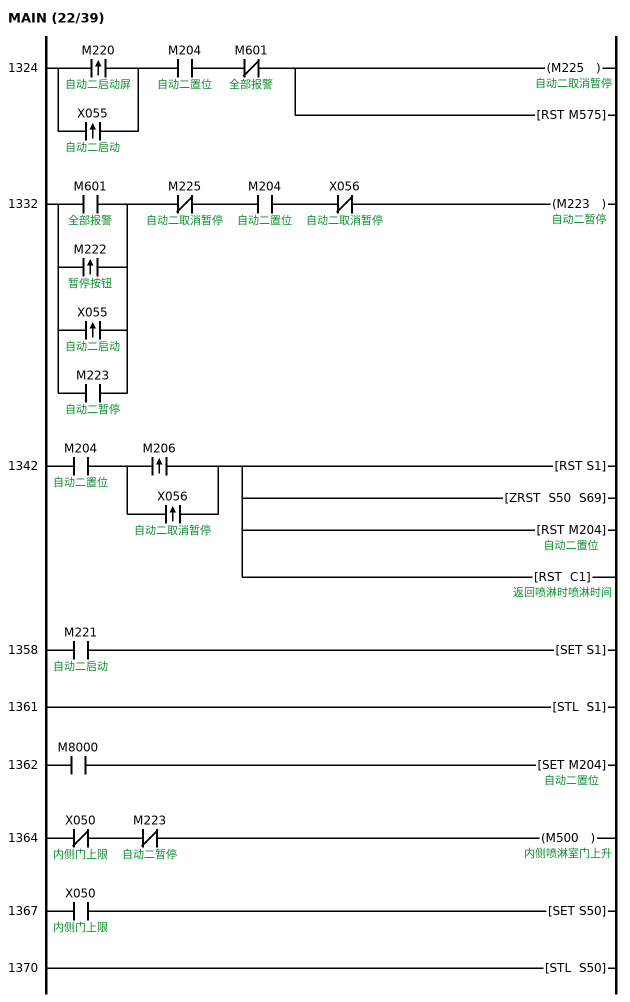
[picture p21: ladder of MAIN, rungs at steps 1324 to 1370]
1324  LDP     M220  ; 自动二启动屏
      ORP     X055  ; 自动二启动
      AND     M204  ; 自动二置位
      ANI     M601  ; 全部报警
      OUT     M225  ; 自动二取消暂停
      RST     M575
1332  LD      M601  ; 全部报警
      ORP     M222  ; 暂停按钮
      ORP     X055  ; 自动二启动
      OR      M223  ; 自动二暂停
      ANI     M225  ; 自动二取消暂停
      AND     M204  ; 自动二置位
      ANI     X056  ; 自动二取消暂停
      OUT     M223  ; 自动二暂停
1342  LD      M204  ; 自动二置位
      LDP     M206
      ORP     X056  ; 自动二取消暂停
      ANB
      RST     S1
      ZRST    S50 S69
      RST     M204  ; 自动二置位
      RST     C1  ; 返回喷淋时喷淋时间
1358  LD      M221  ; 自动二启动
      SET     S1
1361  STL     S1
1362  LD      M8000
      SET     M204  ; 自动二置位
1364  LDI     X050  ; 内侧门上限
      ANI     M223  ; 自动二暂停
      OUT     M500  ; 内侧喷淋室门上升
1367  LD      X050  ; 内侧门上限
      SET     S50
1370  STL     S50
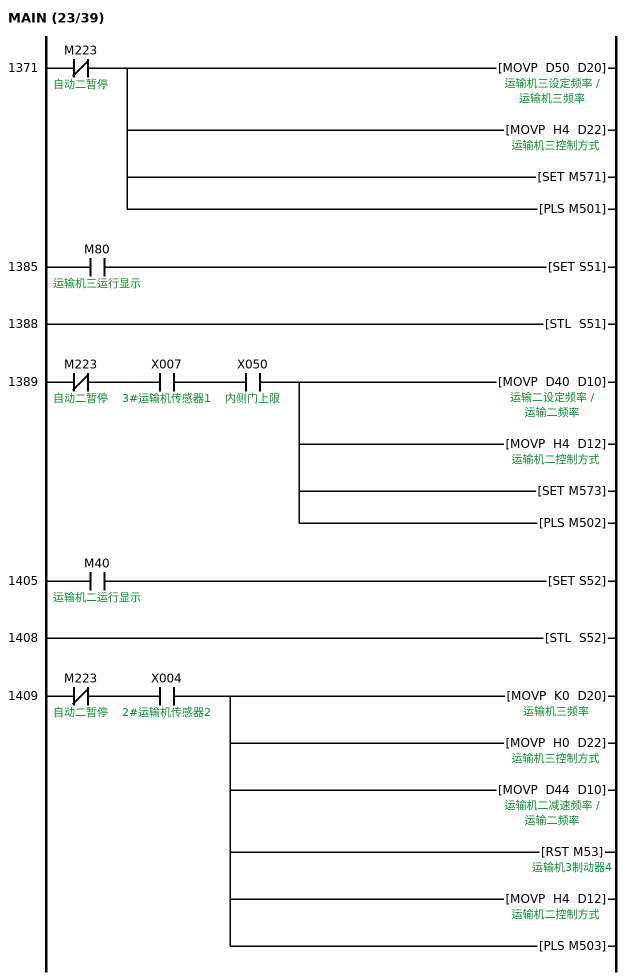
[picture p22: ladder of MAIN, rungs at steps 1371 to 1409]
1371  LDI     M223  ; 自动二暂停
      MOVP    D50 D20
      MOVP    H4 D22
        [note] 3#运输机反转写入
      SET     M571
      PLS     M501
1385  LD      M80  ; 运输机三运行显示
      SET     S51
1388  STL     S51
1389  LDI     M223  ; 自动二暂停
      AND     X007  ; 3#运输机传感器1
      AND     X050  ; 内侧门上限
      MOVP    D40 D10
      MOVP    H4 D12
        [note] 2#运输机反转写入
      SET     M573
      PLS     M502
1405  LD      M40  ; 运输机二运行显示
      SET     S52
1408  STL     S52
1409  LDI     M223  ; 自动二暂停
      AND     X004  ; 2#运输机传感器2
      MOVP    K0 D20
      MOVP    H0 D22
        [note] 3#运输机停止写入
      MOVP    D44 D10
      RST     M53  ; 运输机3制动器4
      MOVP    H4 D12
        [note] 2#运输机反转写入
      PLS     M503
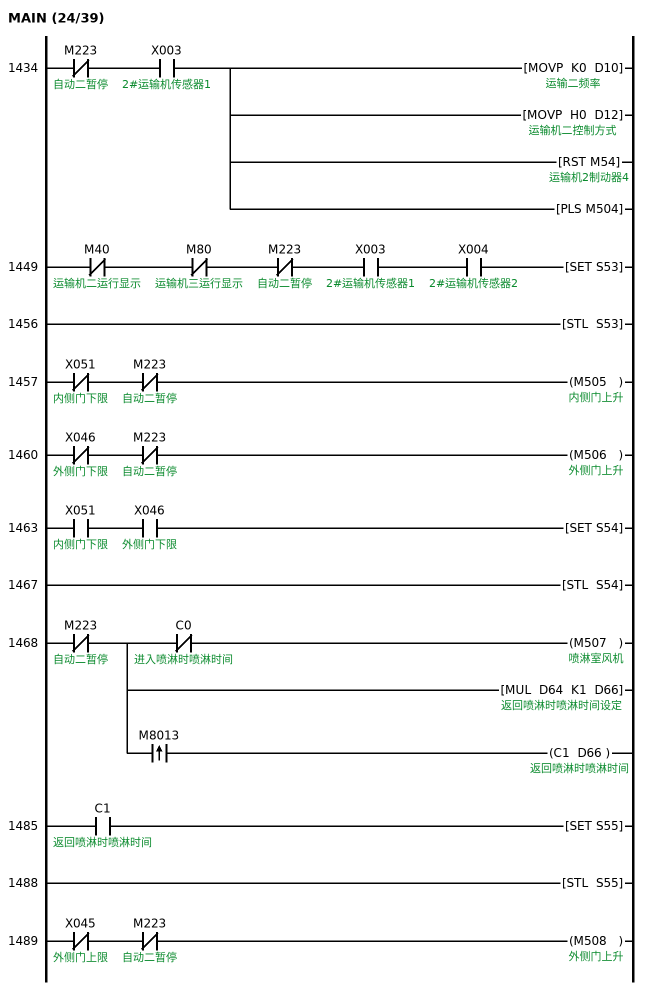
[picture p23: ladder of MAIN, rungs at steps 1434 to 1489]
1434  LDI     M223  ; 自动二暂停
      AND     X003  ; 2#运输机传感器1
      MOVP    K0 D10
      MOVP    H0 D12
        [note] 2#运输机停止写入
      RST     M54  ; 运输机2制动器4
      PLS     M504
1449  LDI     M40  ; 运输机二运行显示
      ANI     M80  ; 运输机三运行显示
      ANI     M223  ; 自动二暂停
      AND     X003  ; 2#运输机传感器1
      AND     X004  ; 2#运输机传感器2
      SET     S53
1456  STL     S53
1457  LDI     X051  ; 内侧门下限
      ANI     M223  ; 自动二暂停
      OUT     M505  ; 内侧门上升
1460  LDI     X046  ; 外侧门下限
      ANI     M223  ; 自动二暂停
      OUT     M506  ; 外侧门上升
1463  LD      X051  ; 内侧门下限
      AND     X046  ; 外侧门下限
      SET     S54
1467  STL     S54
1468  LDI     M223  ; 自动二暂停
      MPS
      ANI     C0  ; 进入喷淋时喷淋时间
      OUT     M507  ; 喷淋室风机
      MPP
      MUL     D64 K1 D66  ; 返回喷淋时喷淋时间设定
      ANDP    M8013
      OUT     C1 D66  ; 返回喷淋时喷淋时间
1485  LD      C1  ; 返回喷淋时喷淋时间
      SET     S55
1488  STL     S55
1489  LDI     X045  ; 外侧门上限
      ANI     M223  ; 自动二暂停
      OUT     M508  ; 外侧门上升
1492  LDI     X024  ; 阻挡电机上限
      ANI     M223  ; 自动二暂停
      OUT     M513  ; 阻挡电机反转
1495  LD      X045  ; 外侧门上限
      AND     X024  ; 阻挡电机上限
      SET     S56
1499  STL     S56
1500  LDI     M223  ; 自动二暂停
      MOVP    D30 D0
      MOVP    H4 D2
        [note] 1#运输机反转写入
      MOVP    D40 D10
      MOVP    H4 D12
        [note] 2#运输机反转写入
      SET     M572
      PLS     M509
1524  LD      M40  ; 运输机二运行显示
      AND     M10  ; 运输机一运行显示
      SET     S57
1528  STL     S57
1529  LDI     M223  ; 自动二暂停
      ANI     X000  ; 1#运输机传感器1
      ANDP    X001  ; 1#运输机传感器2
      MOVP    D34 D0
      MOVP    H4 D2
        [note] 1#运输机反转写入
      MOVP    K0 D10
      MOVP    H0 D12
        [note] 2#运输机停止写入
      RST     M55  ; 运输机2制动器5
      OUT     M510
1555  LDI     X046  ; 外侧门下限
      ANI     M223  ; 自动二暂停
      AND     X000  ; 1#运输机传感器1
      OUT     M511  ; 外侧门上升
1559  LDI     M223  ; 自动二暂停
      AND     X001  ; 1#运输机传感器2
      ANDP    X000  ; 1#运输机传感器1
      MOVP    K0 D0
      MOVP    H0 D2
        [note] 1#运输机停止写入
      RST     M56  ; 运输机1制动器5
      PLS     M512
1576  LDI     M10  ; 运输机一运行显示
      ANI     M40  ; 运输机二运行显示
      AND     X046  ; 外侧门下限
      AND     X000  ; 1#运输机传感器1
      AND     X001  ; 1#运输机传感器2
      ANI     M223  ; 自动二暂停
      SET     S58
1584  STL     S58
1585  LD      M8000
      RST     S1
      ZRST    S50 S69
      RST     M204  ; 自动二置位
      ZRST    M53 M56
      ZRST    M571 M573
      RST     C1  ; 返回喷淋时喷淋时间
1606  RET
1607  LDF     M211  ; 暂停
      ORF     M223  ; 自动二暂停
      AND     M250
      LD      M203  ; 自动一置位
      OR      M204  ; 自动二置位
      ANB
      OUT     M240
      RST     M250
      MOV     H2 D2
        [note] 1#运输机正转写入
1622  LDF     M211  ; 暂停
      ORF     M223  ; 自动二暂停
      AND     M251
      LD      M203  ; 自动一置位
      OR      M204  ; 自动二置位
      ANB
      OUT     M241
      RST     M251
      MOV     H2 D12
        [note] 2#运输机正转写入
1637  LDF     M211  ; 暂停
      ORF     M223  ; 自动二暂停
      AND     M252
      LD      M204  ; 自动二置位
      OR      M203  ; 自动一置位
      ANB
      OUT     M242
      RST     M252
      MOV     H2 D22
        [note] 3#运输机正转写入
1652  LDF     M211  ; 暂停
      ORF     M223  ; 自动二暂停
      AND     M253
      LD      M203  ; 自动一置位
      OR      M204  ; 自动二置位
      ANB
      OUT     M243
      RST     M253
      MOV     H4 D2
        [note] 1#运输机反转写入
1667  LDF     M211  ; 暂停
      ORF     M223  ; 自动二暂停
      AND     M254
      LD      M203  ; 自动一置位
      OR      M204  ; 自动二置位
      ANB
      OUT     M244
      RST     M254
      MOV     H4 D12
        [note] 2#运输机反转写入
1682  LDF     M211  ; 暂停
      ORF     M223  ; 自动二暂停
      AND     M255
      LD      M203  ; 自动一置位
      OR      M204  ; 自动二置位
      ANB
      OUT     M245
      RST     M255
      MOV     H4 D22
        [note] ;3#运输机反转写入
1697  LD      M203  ; 自动一置位
      ANDP    M211  ; 暂停
      LD      M204  ; 自动二置位
      ANDP    M223  ; 自动二暂停
      ORB
      AND     M11
      SET     M250
      MOV     H0 D2
        [note] 1#运输机停止写入
1711  LD      M203  ; 自动一置位
      ANDP    M211  ; 暂停
      LD      M204  ; 自动二置位
      ANDP    M223  ; 自动二暂停
      ORB
      AND     M41
      SET     M251
      MOV     H0 D12
        [note] 2#运输机停止写入
1725  LD      M203  ; 自动一置位
      ANDP    M211  ; 暂停
      LD      M204  ; 自动二置位
      ANDP    M223  ; 自动二暂停
      ORB
      AND     M81
      SET     M252
      MOV     H0 D22
        [note] 3#运输机停止写入
1739  LD      M203  ; 自动一置位
      ANDP    M211  ; 暂停
      LD      M204  ; 自动二置位
      ANDP    M223  ; 自动二暂停
      ORB
      AND     M12
      SET     M253
      MOV     H0 D22
        [note] 3#运输机停止写入
1753  LD      M203  ; 自动一置位
      ANDP    M211  ; 暂停
      LD      M204  ; 自动二置位
      ANDP    M223  ; 自动二暂停
      ORB
      AND     M42
      SET     M254
      MOV     H0 D12
        [note] 2#运输机停止写入
1767  LD      M203  ; 自动一置位
      ANDP    M211  ; 暂停
      LD      M204  ; 自动二置位
      ANDP    M223  ; 自动二暂停
      ORB
      AND     M82
      SET     M255
      MOV     H0 D22
        [note] 3#运输机停止写入
1781  LDP     X057  ; 内侧复位按钮
      OUT     M610  ; 报警复位
      ZRST    M50 M69
      ZRST    M570 M575
1794  LDP     M600  ; 报警复位
      ZRST    M50 M69
      ZRST    M570 M575
1806  LD      M10  ; 运输机一运行显示
      OR      M40  ; 运输机二运行显示
      AND     X012  ; 外侧龙门架传感器1
      OR      T100  ; 外侧龙门架超高报警
      ANI     M600  ; 报警复位
      ANI     M610  ; 报警复位
      OUT     T100 K1  ; 外侧龙门架超高报警
1815  LD      M40  ; 运输机二运行显示
      OR      M80  ; 运输机三运行显示
      AND     X016  ; 内侧龙门架传感器1
      OR      T101  ; 内侧龙门架超高报警
      ANI     M600  ; 报警复位
      ANI     M610  ; 报警复位
      OUT     T101 K1  ; 内侧龙门架超高报警
1824  LD      X026  ; 外侧面板急停开关
      OR      T107  ; 外侧面板急停开关
      ANI     M600  ; 报警复位
      ANI     M610  ; 报警复位
      OUT     T107 K1  ; 外侧面板急停开关
1831  LD      X030  ; 内侧面板急停开关
      OR      T109  ; 内侧面板急停开关
      ANI     M600  ; 报警复位
      ANI     M610  ; 报警复位
      OUT     T109 K1  ; 内侧面板急停开关
1838  LDI     X046  ; 外侧门下限
      ANI     X051  ; 内侧门下限
      OR      T111  ; 内外风淋门都打开报警
      ANI     M600  ; 报警复位
      ANI     M610  ; 报警复位
      ANI     M8000
      OUT     T111 K1  ; 内外风淋门都打开报警
1847  LD      X000  ; 1#运输机传感器1
      OR      X001  ; 1#运输机传感器2
      OR      X002  ; 运输机一三号传感器
      LD      X010  ; 运输机三传感器二
      OR      X011  ; 运输机三传感器三
      OR      X007  ; 3#运输机传感器1
      ANB
      OUT     M620
1855  LD      X000  ; 1#运输机传感器1
      OR      X001  ; 1#运输机传感器2
      OR      X010  ; 运输机三传感器二
      OR      X011  ; 运输机三传感器三
      LD      X003  ; 2#运输机传感器1
      OR      X004  ; 2#运输机传感器2
      OR      X005  ; 2#运输机传感器3
      OR      X006  ; 2#运输机传感器4
      ANB
      OUT     M621
1865  LD      X002  ; 运输机一三号传感器
      LD      X005  ; 2#运输机传感器3
      OR      X006  ; 2#运输机传感器4
      ANB
      OUT     M622
1870  LD      X007  ; 3#运输机传感器1
      LD      X003  ; 2#运输机传感器1
      OR      X004  ; 2#运输机传感器2
      ANB
      OUT     M623
1875  LD      X002  ; 运输机一三号传感器
      OR      X007  ; 3#运输机传感器1
      LD      X000  ; 1#运输机传感器1
      OR      X001  ; 1#运输机传感器2
      ANB
      OUT     M624
1881  LD      X007  ; 3#运输机传感器1
      OR      X002  ; 运输机一三号传感器
      LD      X010  ; 运输机三传感器二
      OR      X011  ; 运输机三传感器三
      ANB
      OUT     M625
1887  LD      M620
      OR      M621
      OR      M622
      OR      M623
      OR      M624
      OR      M625
      OR      T112  ; 存在多个托盘
      ANI     M600  ; 报警复位
      ANI     M610  ; 报警复位
      OUT     T112 K30  ; 存在多个托盘
1899  LD      T100  ; 外侧龙门架超高报警
      OR      T101  ; 内侧龙门架超高报警
      OR      T102  ; 外侧龙门架防夹报警
      OR      T103  ; 内侧龙门架防夹报警
      OR      T104  ; 运输机一变频器报警
      OR      T105  ; 运输机二变频器报警
      OR      T106  ; 运输机三变频器报警
      OR      T107  ; 外侧面板急停开关
      OR      T108  ; 外侧喷淋急停开关
      OR      T109  ; 内侧面板急停开关
      OR      T110  ; 内侧喷淋急停开关
      OR      T111  ; 内外风淋门都打开报警
      OR      T112  ; 存在多个托盘
      OUT     M601  ; 全部报警
1913  LD      M601  ; 全部报警
      OUT     Y014  ; 红灯
      ANI     M602
      AND     M8013
      OUT     Y017  ; 蜂鸣器
1918  LDP     T30  ; 报警复位延时
      AND     M601  ; 全部报警
      SET     M602
1922  LDP     M600  ; 报警复位
      OR      M605
      ORP     M610  ; 报警复位
      OUT     T30 K10  ; 报警复位延时
      ANI     T30  ; 报警复位延时
      OUT     M605
1932  LD      M603
      RST     M602
1934  LDP     T100  ; 外侧龙门架超高报警
      ORP     T101  ; 内侧龙门架超高报警
      ORP     T102  ; 外侧龙门架防夹报警
      ORP     T103  ; 内侧龙门架防夹报警
      ORP     T104  ; 运输机一变频器报警
      ORP     T105  ; 运输机二变频器报警
      ORP     T106  ; 运输机三变频器报警
      ORP     T107  ; 外侧面板急停开关
      ORP     T108  ; 外侧喷淋急停开关
      ORP     T109  ; 内侧面板急停开关
      ORP     T110  ; 内侧喷淋急停开关
      ORP     T111  ; 内外风淋门都打开报警
      ORP     T112  ; 存在多个托盘
      OUT     M603
      MOV     K4 D300  ; 画面寄存器
        [note] 跳转到报警画面
; 开机密码设置============
1966  LD      M8002
      MOV     K2 D300
1972  LDD=    D304 K1234
      AND     M700
      MOVP    K3 D300
      RST     D304
      RST     D305
1993  LD      M203  ; 自动一置位
      OR      M204  ; 自动二置位
      OR      M289  ; 全部手动
      ANI     M601  ; 全部报警
      OUT     Y016  ; 绿灯
1998  LDI     Y016  ; 绿灯
      ANI     Y014  ; 红灯
      OUT     Y015  ; 黄灯
2001  LD      M310  ; 阻挡电机下降
      OR      M132  ; 阻挡电机正转
      OR      M322  ; 阻挡电机下降
      OR      M513  ; 阻挡电机反转
      OR      M192  ; 阻挡电机反转
      OUT     Y020  ; 阻挡电机
2007  LD      M313  ; 外侧门上升
      OR      M508  ; 外侧门上升
      OR      M152  ; 外侧喷淋门上升
      OR      M320  ; 外侧门上升
      OR      M506  ; 外侧门上升
      OR      M511  ; 外侧门上升
      OR      M162  ; 外侧喷淋门下降
      OR      M8000
      OUT     Y025  ; 外侧喷淋门电源
2016  LD      X012  ; 外侧龙门架传感器1
      OR      X013  ; 外侧龙门架传感器2
      OR      X014  ; 外侧龙门架传感器3
      OR      X015  ; 外侧龙门架传感器4
      AND     X004  ; 2#运输机传感器2
      AND     X005  ; 2#运输机传感器3
      AND     X006  ; 2#运输机传感器4
      AND     M351
      OUT     M350
2025  LD      X002  ; 运输机一三号传感器
      AND     X003  ; 2#运输机传感器1
      OUT     M357
2028  LDP     M320  ; 外侧门上升
      OR      M351
      ANI     M323  ; 喷淋室风机
      OUT     M351
2033  LDP     M508  ; 外侧门上升
      OR      M353
      ANI     T15
      OUT     M353
      ANI     X012  ; 外侧龙门架传感器1
      ANI     X013  ; 外侧龙门架传感器2
      ANI     X014  ; 外侧龙门架传感器3
      ANI     X015  ; 外侧龙门架传感器4
      ANI     X045  ; 外侧门上限
      OUT     T15 K100
2046  LD      X012  ; 外侧龙门架传感器1
      OR      X013  ; 外侧龙门架传感器2
      OR      X014  ; 外侧龙门架传感器3
      OR      X015  ; 外侧龙门架传感器4
      AND     M353
      OUT     M352
2052  LDP     M152  ; 外侧喷淋门上升
      ORP     M313  ; 外侧门上升
      ORP     M508  ; 外侧门上升
      LDI     M350
      ANI     M352
      AND     Y026  ; 外侧喷淋门方向
      ANI     M357
      ORB
      ANI     M162  ; 外侧喷淋门下降
      ANI     M320  ; 外侧门上升
      ANI     M506  ; 外侧门上升
      ANI     M511  ; 外侧门上升
      LDI     M350
      ANI     M352
      ANI     M357
      INV
      ORB
      OUT     Y026  ; 外侧喷淋门方向
2073  LD      M60  ; 运输机—制动器中继
      OR      M50  ; 运输机—制动器(自动）2
      OR      M68  ; 运输机—制动器(自动）1
      OR      M61  ; 运输机一制动器中继1
      OR      M56  ; 运输机1制动器5
      OUT     Y034  ; 运输机一制动器
2079  LD      M62  ; 运输机二制动器1
      OR      M63  ; 运输机二制动器中继2
      OR      M69  ; 运输机二制动器(自动）1
      OR      M66  ; 运输机二制动器3
      OR      M54  ; 运输机2制动器4
      OR      M67  ; 运输机二制动器4
      OR      M51  ; 运输机二制动器(自动）2
      OR      M55  ; 运输机2制动器5
      OUT     Y035  ; 运输机二制动器
2088  LD      M64  ; 运输机三制动中继1
      OR      M52  ; 运输机三制动器(自动）1
      OR      M53  ; 运输机3制动器4
      OR      M65  ; 运输机三制动中继2
      OUT     Y036  ; 运输机三制动器
2093  LDP     M172  ; 内侧喷淋室门上升
      ORP     M324  ; 内侧喷淋室门上升
      ORP     M500  ; 内侧喷淋室门上升
      OR      Y024  ; 内侧喷淋门方向
      ANI     M182  ; 内侧喷淋门下降
      ANI     M321  ; 内侧门上升
      ANI     M330
      ANI     M505  ; 内侧门上升
      OUT     Y024  ; 内侧喷淋门方向
2105  LD      M323  ; 喷淋室风机
      OR      M507  ; 喷淋室风机
      OR      M142  ; 喷淋室风机
      OR      M135  ; 喷淋电机
      OUT     Y022  ; 喷淋电机
2110  LD      M324  ; 内侧喷淋室门上升
      OR      M500  ; 内侧喷淋室门上升
      OR      M172  ; 内侧喷淋室门上升
      OR      M321  ; 内侧门上升
      OR      M505  ; 内侧门上升
      OR      M182  ; 内侧喷淋门下降
      OR      M330
      OR      M8000
      OUT     Y023  ; 内侧喷淋门电源
2119  LDI     M202  ; 手动
      OUT     Y012  ; 自动运行指示灯
2121  LD      M202  ; 手动
      OUT     Y013  ; 手动运行指示灯
2123  LD      M102  ; 手动运输机一正转
      OR      M105  ; 运输机一手动反转
      OR      M112  ; 运输机二手动正转
      OR      M115  ; 运输机二手动反转
      OR      M122  ; 运输机三手动正转
      OR      M125  ; 运输机三手动反转
      OR      M132  ; 阻挡电机正转
      OR      M135  ; 喷淋电机
      OR      M142  ; 喷淋室风机
      OR      M152  ; 外侧喷淋门上升
      OR      M162  ; 外侧喷淋门下降
      OR      M172  ; 内侧喷淋室门上升
      OR      M182  ; 内侧喷淋门下降
      OR      M192  ; 阻挡电机反转
      OUT     M289  ; 全部手动
2138  LDP     X044  ; 自动一停止
      LD      M203  ; 自动一置位
      OR      M576
      ANB
      LDP     M206
      AND     M204  ; 自动二置位
      ORB
      OUT     M228
      MOV     H0 D2
      MOV     H0 D12
      MOV     H0 D22
2163  LD      M323  ; 喷淋室风机
      MOV     C0 D302
2169  LD      M507  ; 喷淋室风机
      MOV     C1 D302
2175  LD      M142  ; 喷淋室风机
      MPS
      ANDP    M8013
      OUT     C2 K30000
      MPP
      MOV     C2 D302
2188  LDF     M142  ; 喷淋室风机
      RST     C2
2192  LD      M135  ; 喷淋电机
      MPS
      ANDP    M8013
      OUT     C3 K30000
      MPP
      MOV     C3 D302
2205  LDF     M135  ; 喷淋电机
      RST     C3
2209  LD      M203  ; 自动一置位
      OR      M204  ; 自动二置位
      OR      M199
      OUT     Y021  ; 照明
2213  LD      M204  ; 自动二置位
      AND     M223  ; 自动二暂停
      AND     M8013
      LD      M204  ; 自动二置位
      ANI     M223  ; 自动二暂停
      ORB
      OUT     Y031  ; 自动二指示灯
2220  LD      M203  ; 自动一置位
      AND     M211  ; 暂停
      AND     M8013
      LD      M203  ; 自动一置位
      ANI     M211  ; 暂停
      ORB
      OUT     Y010  ; 自动一指示灯
2227  LD      M203  ; 自动一置位
      AND     M211  ; 暂停
      AND     X044  ; 自动一停止
      OR      M601  ; 全部报警
      LD      M204  ; 自动二置位
      AND     M223  ; 自动二暂停
      LD      X056  ; 自动二取消暂停
      OR      M222  ; 暂停按钮
      ANB
      ORB
      MOVP    H0 D2
      MOVP    H0 D12
      MOVP    H0 D22
      ZRST    M60 M69
      ZRST    M570 M575
      MPS
      AND     X002  ; 运输机一三号传感器
      AND     X003  ; 2#运输机传感器1
      AND     X004  ; 2#运输机传感器2
      OUT     M580
      MPP
      PLS     M550
2270  LD      M570
      SET     M51  ; 运输机二制动器(自动）2
      SET     M52  ; 运输机三制动器(自动）1
2273  LD      M571
      SET     M53  ; 运输机3制动器4
2275  LD      M572
      SET     M56  ; 运输机1制动器5
      SET     M55  ; 运输机2制动器5
2278  LD      M573
      SET     M54  ; 运输机2制动器4
2280  END
END_PROGRAM

// device comments not shown above
X031  ; 内侧喷淋防夹信号
